VERSION 5.8 ;
BUSBITCHARS "[]" ;
DIVIDERCHAR "/" ;
UNITS
    DATABASE MICRONS 1000 ;
END UNITS

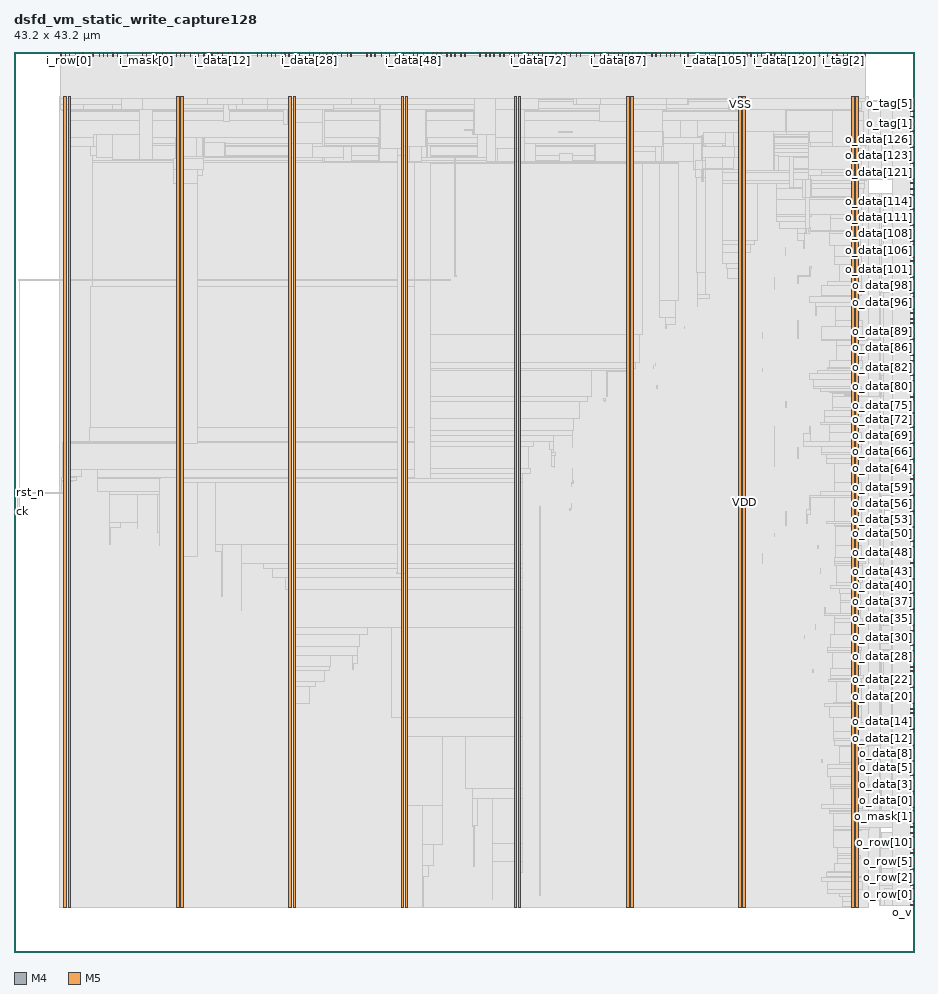
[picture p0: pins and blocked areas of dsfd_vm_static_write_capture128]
MACRO dsfd_vm_static_write_capture128
  FOREIGN dsfd_vm_static_write_capture128 0 0 ;
  CLASS BLOCK ;
  SIZE 43.2 BY 43.2 ;
  PIN ck
    DIRECTION INPUT ;
    USE SIGNAL ;
    PORT
      LAYER M4 ;
        RECT  0 21.12 0.192 21.144 ;
    END
  END ck
  PIN i_data[0]
    DIRECTION INPUT ;
    USE SIGNAL ;
    PORT
      LAYER M5 ;
        RECT  7.296 43.008 7.32 43.2 ;
    END
  END i_data[0]
  PIN i_data[100]
    DIRECTION INPUT ;
    USE SIGNAL ;
    PORT
      LAYER M5 ;
        RECT  31.968 43.008 31.992 43.2 ;
    END
  END i_data[100]
  PIN i_data[101]
    DIRECTION INPUT ;
    USE SIGNAL ;
    PORT
      LAYER M5 ;
        RECT  32.16 43.008 32.184 43.2 ;
    END
  END i_data[101]
  PIN i_data[102]
    DIRECTION INPUT ;
    USE SIGNAL ;
    PORT
      LAYER M5 ;
        RECT  32.352 43.008 32.376 43.2 ;
    END
  END i_data[102]
  PIN i_data[103]
    DIRECTION INPUT ;
    USE SIGNAL ;
    PORT
      LAYER M5 ;
        RECT  33.168 43.008 33.192 43.2 ;
    END
  END i_data[103]
  PIN i_data[104]
    DIRECTION INPUT ;
    USE SIGNAL ;
    PORT
      LAYER M5 ;
        RECT  33.36 43.008 33.384 43.2 ;
    END
  END i_data[104]
  PIN i_data[105]
    DIRECTION INPUT ;
    USE SIGNAL ;
    PORT
      LAYER M5 ;
        RECT  33.648 43.008 33.672 43.2 ;
    END
  END i_data[105]
  PIN i_data[106]
    DIRECTION INPUT ;
    USE SIGNAL ;
    PORT
      LAYER M5 ;
        RECT  33.84 43.008 33.864 43.2 ;
    END
  END i_data[106]
  PIN i_data[107]
    DIRECTION INPUT ;
    USE SIGNAL ;
    PORT
      LAYER M5 ;
        RECT  34.032 43.008 34.056 43.2 ;
    END
  END i_data[107]
  PIN i_data[108]
    DIRECTION INPUT ;
    USE SIGNAL ;
    PORT
      LAYER M5 ;
        RECT  34.32 43.008 34.344 43.2 ;
    END
  END i_data[108]
  PIN i_data[109]
    DIRECTION INPUT ;
    USE SIGNAL ;
    PORT
      LAYER M5 ;
        RECT  34.512 43.008 34.536 43.2 ;
    END
  END i_data[109]
  PIN i_data[10]
    DIRECTION INPUT ;
    USE SIGNAL ;
    PORT
      LAYER M5 ;
        RECT  9.504 43.008 9.528 43.2 ;
    END
  END i_data[10]
  PIN i_data[110]
    DIRECTION INPUT ;
    USE SIGNAL ;
    PORT
      LAYER M5 ;
        RECT  34.704 43.008 34.728 43.2 ;
    END
  END i_data[110]
  PIN i_data[111]
    DIRECTION INPUT ;
    USE SIGNAL ;
    PORT
      LAYER M5 ;
        RECT  34.992 43.008 35.016 43.2 ;
    END
  END i_data[111]
  PIN i_data[112]
    DIRECTION INPUT ;
    USE SIGNAL ;
    PORT
      LAYER M5 ;
        RECT  35.184 43.008 35.208 43.2 ;
    END
  END i_data[112]
  PIN i_data[113]
    DIRECTION INPUT ;
    USE SIGNAL ;
    PORT
      LAYER M5 ;
        RECT  35.376 43.008 35.4 43.2 ;
    END
  END i_data[113]
  PIN i_data[114]
    DIRECTION INPUT ;
    USE SIGNAL ;
    PORT
      LAYER M5 ;
        RECT  35.664 43.008 35.688 43.2 ;
    END
  END i_data[114]
  PIN i_data[115]
    DIRECTION INPUT ;
    USE SIGNAL ;
    PORT
      LAYER M5 ;
        RECT  35.856 43.008 35.88 43.2 ;
    END
  END i_data[115]
  PIN i_data[116]
    DIRECTION INPUT ;
    USE SIGNAL ;
    PORT
      LAYER M5 ;
        RECT  36.144 43.008 36.168 43.2 ;
    END
  END i_data[116]
  PIN i_data[117]
    DIRECTION INPUT ;
    USE SIGNAL ;
    PORT
      LAYER M5 ;
        RECT  36.336 43.008 36.36 43.2 ;
    END
  END i_data[117]
  PIN i_data[118]
    DIRECTION INPUT ;
    USE SIGNAL ;
    PORT
      LAYER M5 ;
        RECT  36.528 43.008 36.552 43.2 ;
    END
  END i_data[118]
  PIN i_data[119]
    DIRECTION INPUT ;
    USE SIGNAL ;
    PORT
      LAYER M5 ;
        RECT  36.816 43.008 36.84 43.2 ;
    END
  END i_data[119]
  PIN i_data[11]
    DIRECTION INPUT ;
    USE SIGNAL ;
    PORT
      LAYER M5 ;
        RECT  9.792 43.008 9.816 43.2 ;
    END
  END i_data[11]
  PIN i_data[120]
    DIRECTION INPUT ;
    USE SIGNAL ;
    PORT
      LAYER M5 ;
        RECT  37.008 43.008 37.032 43.2 ;
    END
  END i_data[120]
  PIN i_data[121]
    DIRECTION INPUT ;
    USE SIGNAL ;
    PORT
      LAYER M5 ;
        RECT  37.2 43.008 37.224 43.2 ;
    END
  END i_data[121]
  PIN i_data[122]
    DIRECTION INPUT ;
    USE SIGNAL ;
    PORT
      LAYER M5 ;
        RECT  37.488 43.008 37.512 43.2 ;
    END
  END i_data[122]
  PIN i_data[123]
    DIRECTION INPUT ;
    USE SIGNAL ;
    PORT
      LAYER M5 ;
        RECT  37.68 43.008 37.704 43.2 ;
    END
  END i_data[123]
  PIN i_data[124]
    DIRECTION INPUT ;
    USE SIGNAL ;
    PORT
      LAYER M5 ;
        RECT  37.872 43.008 37.896 43.2 ;
    END
  END i_data[124]
  PIN i_data[125]
    DIRECTION INPUT ;
    USE SIGNAL ;
    PORT
      LAYER M5 ;
        RECT  38.64 43.008 38.664 43.2 ;
    END
  END i_data[125]
  PIN i_data[126]
    DIRECTION INPUT ;
    USE SIGNAL ;
    PORT
      LAYER M5 ;
        RECT  38.832 43.008 38.856 43.2 ;
    END
  END i_data[126]
  PIN i_data[127]
    DIRECTION INPUT ;
    USE SIGNAL ;
    PORT
      LAYER M5 ;
        RECT  39.024 43.008 39.048 43.2 ;
    END
  END i_data[127]
  PIN i_data[12]
    DIRECTION INPUT ;
    USE SIGNAL ;
    PORT
      LAYER M5 ;
        RECT  9.984 43.008 10.008 43.2 ;
    END
  END i_data[12]
  PIN i_data[13]
    DIRECTION INPUT ;
    USE SIGNAL ;
    PORT
      LAYER M5 ;
        RECT  10.272 43.008 10.296 43.2 ;
    END
  END i_data[13]
  PIN i_data[14]
    DIRECTION INPUT ;
    USE SIGNAL ;
    PORT
      LAYER M5 ;
        RECT  10.464 43.008 10.488 43.2 ;
    END
  END i_data[14]
  PIN i_data[15]
    DIRECTION INPUT ;
    USE SIGNAL ;
    PORT
      LAYER M5 ;
        RECT  10.656 43.008 10.68 43.2 ;
    END
  END i_data[15]
  PIN i_data[16]
    DIRECTION INPUT ;
    USE SIGNAL ;
    PORT
      LAYER M5 ;
        RECT  10.944 43.008 10.968 43.2 ;
    END
  END i_data[16]
  PIN i_data[17]
    DIRECTION INPUT ;
    USE SIGNAL ;
    PORT
      LAYER M5 ;
        RECT  11.664 43.008 11.688 43.2 ;
    END
  END i_data[17]
  PIN i_data[18]
    DIRECTION INPUT ;
    USE SIGNAL ;
    PORT
      LAYER M5 ;
        RECT  11.856 43.008 11.88 43.2 ;
    END
  END i_data[18]
  PIN i_data[19]
    DIRECTION INPUT ;
    USE SIGNAL ;
    PORT
      LAYER M5 ;
        RECT  12.144 43.008 12.168 43.2 ;
    END
  END i_data[19]
  PIN i_data[1]
    DIRECTION INPUT ;
    USE SIGNAL ;
    PORT
      LAYER M5 ;
        RECT  7.488 43.008 7.512 43.2 ;
    END
  END i_data[1]
  PIN i_data[20]
    DIRECTION INPUT ;
    USE SIGNAL ;
    PORT
      LAYER M5 ;
        RECT  12.336 43.008 12.36 43.2 ;
    END
  END i_data[20]
  PIN i_data[21]
    DIRECTION INPUT ;
    USE SIGNAL ;
    PORT
      LAYER M5 ;
        RECT  12.528 43.008 12.552 43.2 ;
    END
  END i_data[21]
  PIN i_data[22]
    DIRECTION INPUT ;
    USE SIGNAL ;
    PORT
      LAYER M5 ;
        RECT  12.816 43.008 12.84 43.2 ;
    END
  END i_data[22]
  PIN i_data[23]
    DIRECTION INPUT ;
    USE SIGNAL ;
    PORT
      LAYER M5 ;
        RECT  13.008 43.008 13.032 43.2 ;
    END
  END i_data[23]
  PIN i_data[24]
    DIRECTION INPUT ;
    USE SIGNAL ;
    PORT
      LAYER M5 ;
        RECT  13.2 43.008 13.224 43.2 ;
    END
  END i_data[24]
  PIN i_data[25]
    DIRECTION INPUT ;
    USE SIGNAL ;
    PORT
      LAYER M5 ;
        RECT  13.488 43.008 13.512 43.2 ;
    END
  END i_data[25]
  PIN i_data[26]
    DIRECTION INPUT ;
    USE SIGNAL ;
    PORT
      LAYER M5 ;
        RECT  13.68 43.008 13.704 43.2 ;
    END
  END i_data[26]
  PIN i_data[27]
    DIRECTION INPUT ;
    USE SIGNAL ;
    PORT
      LAYER M5 ;
        RECT  13.968 43.008 13.992 43.2 ;
    END
  END i_data[27]
  PIN i_data[28]
    DIRECTION INPUT ;
    USE SIGNAL ;
    PORT
      LAYER M5 ;
        RECT  14.16 43.008 14.184 43.2 ;
    END
  END i_data[28]
  PIN i_data[29]
    DIRECTION INPUT ;
    USE SIGNAL ;
    PORT
      LAYER M5 ;
        RECT  14.352 43.008 14.376 43.2 ;
    END
  END i_data[29]
  PIN i_data[2]
    DIRECTION INPUT ;
    USE SIGNAL ;
    PORT
      LAYER M5 ;
        RECT  7.776 43.008 7.8 43.2 ;
    END
  END i_data[2]
  PIN i_data[30]
    DIRECTION INPUT ;
    USE SIGNAL ;
    PORT
      LAYER M5 ;
        RECT  14.64 43.008 14.664 43.2 ;
    END
  END i_data[30]
  PIN i_data[31]
    DIRECTION INPUT ;
    USE SIGNAL ;
    PORT
      LAYER M5 ;
        RECT  14.832 43.008 14.856 43.2 ;
    END
  END i_data[31]
  PIN i_data[32]
    DIRECTION INPUT ;
    USE SIGNAL ;
    PORT
      LAYER M5 ;
        RECT  15.024 43.008 15.048 43.2 ;
    END
  END i_data[32]
  PIN i_data[33]
    DIRECTION INPUT ;
    USE SIGNAL ;
    PORT
      LAYER M5 ;
        RECT  15.312 43.008 15.336 43.2 ;
    END
  END i_data[33]
  PIN i_data[34]
    DIRECTION INPUT ;
    USE SIGNAL ;
    PORT
      LAYER M5 ;
        RECT  15.504 43.008 15.528 43.2 ;
    END
  END i_data[34]
  PIN i_data[35]
    DIRECTION INPUT ;
    USE SIGNAL ;
    PORT
      LAYER M5 ;
        RECT  15.696 43.008 15.72 43.2 ;
    END
  END i_data[35]
  PIN i_data[36]
    DIRECTION INPUT ;
    USE SIGNAL ;
    PORT
      LAYER M5 ;
        RECT  15.984 43.008 16.008 43.2 ;
    END
  END i_data[36]
  PIN i_data[37]
    DIRECTION INPUT ;
    USE SIGNAL ;
    PORT
      LAYER M5 ;
        RECT  16.176 43.008 16.2 43.2 ;
    END
  END i_data[37]
  PIN i_data[38]
    DIRECTION INPUT ;
    USE SIGNAL ;
    PORT
      LAYER M5 ;
        RECT  16.944 43.008 16.968 43.2 ;
    END
  END i_data[38]
  PIN i_data[39]
    DIRECTION INPUT ;
    USE SIGNAL ;
    PORT
      LAYER M5 ;
        RECT  17.136 43.008 17.16 43.2 ;
    END
  END i_data[39]
  PIN i_data[3]
    DIRECTION INPUT ;
    USE SIGNAL ;
    PORT
      LAYER M5 ;
        RECT  7.968 43.008 7.992 43.2 ;
    END
  END i_data[3]
  PIN i_data[40]
    DIRECTION INPUT ;
    USE SIGNAL ;
    PORT
      LAYER M5 ;
        RECT  17.328 43.008 17.352 43.2 ;
    END
  END i_data[40]
  PIN i_data[41]
    DIRECTION INPUT ;
    USE SIGNAL ;
    PORT
      LAYER M5 ;
        RECT  17.616 43.008 17.64 43.2 ;
    END
  END i_data[41]
  PIN i_data[42]
    DIRECTION INPUT ;
    USE SIGNAL ;
    PORT
      LAYER M5 ;
        RECT  17.808 43.008 17.832 43.2 ;
    END
  END i_data[42]
  PIN i_data[43]
    DIRECTION INPUT ;
    USE SIGNAL ;
    PORT
      LAYER M5 ;
        RECT  18 43.008 18.024 43.2 ;
    END
  END i_data[43]
  PIN i_data[44]
    DIRECTION INPUT ;
    USE SIGNAL ;
    PORT
      LAYER M5 ;
        RECT  18.288 43.008 18.312 43.2 ;
    END
  END i_data[44]
  PIN i_data[45]
    DIRECTION INPUT ;
    USE SIGNAL ;
    PORT
      LAYER M5 ;
        RECT  18.48 43.008 18.504 43.2 ;
    END
  END i_data[45]
  PIN i_data[46]
    DIRECTION INPUT ;
    USE SIGNAL ;
    PORT
      LAYER M5 ;
        RECT  18.672 43.008 18.696 43.2 ;
    END
  END i_data[46]
  PIN i_data[47]
    DIRECTION INPUT ;
    USE SIGNAL ;
    PORT
      LAYER M5 ;
        RECT  18.96 43.008 18.984 43.2 ;
    END
  END i_data[47]
  PIN i_data[48]
    DIRECTION INPUT ;
    USE SIGNAL ;
    PORT
      LAYER M5 ;
        RECT  19.152 43.008 19.176 43.2 ;
    END
  END i_data[48]
  PIN i_data[49]
    DIRECTION INPUT ;
    USE SIGNAL ;
    PORT
      LAYER M5 ;
        RECT  19.344 43.008 19.368 43.2 ;
    END
  END i_data[49]
  PIN i_data[4]
    DIRECTION INPUT ;
    USE SIGNAL ;
    PORT
      LAYER M5 ;
        RECT  8.16 43.008 8.184 43.2 ;
    END
  END i_data[4]
  PIN i_data[50]
    DIRECTION INPUT ;
    USE SIGNAL ;
    PORT
      LAYER M5 ;
        RECT  19.632 43.008 19.656 43.2 ;
    END
  END i_data[50]
  PIN i_data[51]
    DIRECTION INPUT ;
    USE SIGNAL ;
    PORT
      LAYER M5 ;
        RECT  19.824 43.008 19.848 43.2 ;
    END
  END i_data[51]
  PIN i_data[52]
    DIRECTION INPUT ;
    USE SIGNAL ;
    PORT
      LAYER M5 ;
        RECT  20.112 43.008 20.136 43.2 ;
    END
  END i_data[52]
  PIN i_data[53]
    DIRECTION INPUT ;
    USE SIGNAL ;
    PORT
      LAYER M5 ;
        RECT  20.304 43.008 20.328 43.2 ;
    END
  END i_data[53]
  PIN i_data[54]
    DIRECTION INPUT ;
    USE SIGNAL ;
    PORT
      LAYER M5 ;
        RECT  20.496 43.008 20.52 43.2 ;
    END
  END i_data[54]
  PIN i_data[55]
    DIRECTION INPUT ;
    USE SIGNAL ;
    PORT
      LAYER M5 ;
        RECT  20.784 43.008 20.808 43.2 ;
    END
  END i_data[55]
  PIN i_data[56]
    DIRECTION INPUT ;
    USE SIGNAL ;
    PORT
      LAYER M5 ;
        RECT  20.976 43.008 21 43.2 ;
    END
  END i_data[56]
  PIN i_data[57]
    DIRECTION INPUT ;
    USE SIGNAL ;
    PORT
      LAYER M5 ;
        RECT  21.168 43.008 21.192 43.2 ;
    END
  END i_data[57]
  PIN i_data[58]
    DIRECTION INPUT ;
    USE SIGNAL ;
    PORT
      LAYER M5 ;
        RECT  21.456 43.008 21.48 43.2 ;
    END
  END i_data[58]
  PIN i_data[59]
    DIRECTION INPUT ;
    USE SIGNAL ;
    PORT
      LAYER M5 ;
        RECT  21.648 43.008 21.672 43.2 ;
    END
  END i_data[59]
  PIN i_data[5]
    DIRECTION INPUT ;
    USE SIGNAL ;
    PORT
      LAYER M5 ;
        RECT  8.448 43.008 8.472 43.2 ;
    END
  END i_data[5]
  PIN i_data[60]
    DIRECTION INPUT ;
    USE SIGNAL ;
    PORT
      LAYER M5 ;
        RECT  22.368 43.008 22.392 43.2 ;
    END
  END i_data[60]
  PIN i_data[61]
    DIRECTION INPUT ;
    USE SIGNAL ;
    PORT
      LAYER M5 ;
        RECT  22.656 43.008 22.68 43.2 ;
    END
  END i_data[61]
  PIN i_data[62]
    DIRECTION INPUT ;
    USE SIGNAL ;
    PORT
      LAYER M5 ;
        RECT  22.848 43.008 22.872 43.2 ;
    END
  END i_data[62]
  PIN i_data[63]
    DIRECTION INPUT ;
    USE SIGNAL ;
    PORT
      LAYER M5 ;
        RECT  23.04 43.008 23.064 43.2 ;
    END
  END i_data[63]
  PIN i_data[64]
    DIRECTION INPUT ;
    USE SIGNAL ;
    PORT
      LAYER M5 ;
        RECT  23.328 43.008 23.352 43.2 ;
    END
  END i_data[64]
  PIN i_data[65]
    DIRECTION INPUT ;
    USE SIGNAL ;
    PORT
      LAYER M5 ;
        RECT  23.52 43.008 23.544 43.2 ;
    END
  END i_data[65]
  PIN i_data[66]
    DIRECTION INPUT ;
    USE SIGNAL ;
    PORT
      LAYER M5 ;
        RECT  23.808 43.008 23.832 43.2 ;
    END
  END i_data[66]
  PIN i_data[67]
    DIRECTION INPUT ;
    USE SIGNAL ;
    PORT
      LAYER M5 ;
        RECT  24 43.008 24.024 43.2 ;
    END
  END i_data[67]
  PIN i_data[68]
    DIRECTION INPUT ;
    USE SIGNAL ;
    PORT
      LAYER M5 ;
        RECT  24.192 43.008 24.216 43.2 ;
    END
  END i_data[68]
  PIN i_data[69]
    DIRECTION INPUT ;
    USE SIGNAL ;
    PORT
      LAYER M5 ;
        RECT  24.48 43.008 24.504 43.2 ;
    END
  END i_data[69]
  PIN i_data[6]
    DIRECTION INPUT ;
    USE SIGNAL ;
    PORT
      LAYER M5 ;
        RECT  8.64 43.008 8.664 43.2 ;
    END
  END i_data[6]
  PIN i_data[70]
    DIRECTION INPUT ;
    USE SIGNAL ;
    PORT
      LAYER M5 ;
        RECT  24.672 43.008 24.696 43.2 ;
    END
  END i_data[70]
  PIN i_data[71]
    DIRECTION INPUT ;
    USE SIGNAL ;
    PORT
      LAYER M5 ;
        RECT  24.864 43.008 24.888 43.2 ;
    END
  END i_data[71]
  PIN i_data[72]
    DIRECTION INPUT ;
    USE SIGNAL ;
    PORT
      LAYER M5 ;
        RECT  25.152 43.008 25.176 43.2 ;
    END
  END i_data[72]
  PIN i_data[73]
    DIRECTION INPUT ;
    USE SIGNAL ;
    PORT
      LAYER M5 ;
        RECT  25.344 43.008 25.368 43.2 ;
    END
  END i_data[73]
  PIN i_data[74]
    DIRECTION INPUT ;
    USE SIGNAL ;
    PORT
      LAYER M5 ;
        RECT  25.536 43.008 25.56 43.2 ;
    END
  END i_data[74]
  PIN i_data[75]
    DIRECTION INPUT ;
    USE SIGNAL ;
    PORT
      LAYER M5 ;
        RECT  25.824 43.008 25.848 43.2 ;
    END
  END i_data[75]
  PIN i_data[76]
    DIRECTION INPUT ;
    USE SIGNAL ;
    PORT
      LAYER M5 ;
        RECT  26.016 43.008 26.04 43.2 ;
    END
  END i_data[76]
  PIN i_data[77]
    DIRECTION INPUT ;
    USE SIGNAL ;
    PORT
      LAYER M5 ;
        RECT  26.304 43.008 26.328 43.2 ;
    END
  END i_data[77]
  PIN i_data[78]
    DIRECTION INPUT ;
    USE SIGNAL ;
    PORT
      LAYER M5 ;
        RECT  26.496 43.008 26.52 43.2 ;
    END
  END i_data[78]
  PIN i_data[79]
    DIRECTION INPUT ;
    USE SIGNAL ;
    PORT
      LAYER M5 ;
        RECT  26.688 43.008 26.712 43.2 ;
    END
  END i_data[79]
  PIN i_data[7]
    DIRECTION INPUT ;
    USE SIGNAL ;
    PORT
      LAYER M5 ;
        RECT  8.832 43.008 8.856 43.2 ;
    END
  END i_data[7]
  PIN i_data[80]
    DIRECTION INPUT ;
    USE SIGNAL ;
    PORT
      LAYER M5 ;
        RECT  26.976 43.008 27 43.2 ;
    END
  END i_data[80]
  PIN i_data[81]
    DIRECTION INPUT ;
    USE SIGNAL ;
    PORT
      LAYER M5 ;
        RECT  27.168 43.008 27.192 43.2 ;
    END
  END i_data[81]
  PIN i_data[82]
    DIRECTION INPUT ;
    USE SIGNAL ;
    PORT
      LAYER M5 ;
        RECT  27.84 43.008 27.864 43.2 ;
    END
  END i_data[82]
  PIN i_data[83]
    DIRECTION INPUT ;
    USE SIGNAL ;
    PORT
      LAYER M5 ;
        RECT  28.128 43.008 28.152 43.2 ;
    END
  END i_data[83]
  PIN i_data[84]
    DIRECTION INPUT ;
    USE SIGNAL ;
    PORT
      LAYER M5 ;
        RECT  28.32 43.008 28.344 43.2 ;
    END
  END i_data[84]
  PIN i_data[85]
    DIRECTION INPUT ;
    USE SIGNAL ;
    PORT
      LAYER M5 ;
        RECT  28.512 43.008 28.536 43.2 ;
    END
  END i_data[85]
  PIN i_data[86]
    DIRECTION INPUT ;
    USE SIGNAL ;
    PORT
      LAYER M5 ;
        RECT  28.8 43.008 28.824 43.2 ;
    END
  END i_data[86]
  PIN i_data[87]
    DIRECTION INPUT ;
    USE SIGNAL ;
    PORT
      LAYER M5 ;
        RECT  28.992 43.008 29.016 43.2 ;
    END
  END i_data[87]
  PIN i_data[88]
    DIRECTION INPUT ;
    USE SIGNAL ;
    PORT
      LAYER M5 ;
        RECT  29.184 43.008 29.208 43.2 ;
    END
  END i_data[88]
  PIN i_data[89]
    DIRECTION INPUT ;
    USE SIGNAL ;
    PORT
      LAYER M5 ;
        RECT  29.472 43.008 29.496 43.2 ;
    END
  END i_data[89]
  PIN i_data[8]
    DIRECTION INPUT ;
    USE SIGNAL ;
    PORT
      LAYER M5 ;
        RECT  9.12 43.008 9.144 43.2 ;
    END
  END i_data[8]
  PIN i_data[90]
    DIRECTION INPUT ;
    USE SIGNAL ;
    PORT
      LAYER M5 ;
        RECT  29.664 43.008 29.688 43.2 ;
    END
  END i_data[90]
  PIN i_data[91]
    DIRECTION INPUT ;
    USE SIGNAL ;
    PORT
      LAYER M5 ;
        RECT  29.952 43.008 29.976 43.2 ;
    END
  END i_data[91]
  PIN i_data[92]
    DIRECTION INPUT ;
    USE SIGNAL ;
    PORT
      LAYER M5 ;
        RECT  30.144 43.008 30.168 43.2 ;
    END
  END i_data[92]
  PIN i_data[93]
    DIRECTION INPUT ;
    USE SIGNAL ;
    PORT
      LAYER M5 ;
        RECT  30.336 43.008 30.36 43.2 ;
    END
  END i_data[93]
  PIN i_data[94]
    DIRECTION INPUT ;
    USE SIGNAL ;
    PORT
      LAYER M5 ;
        RECT  30.624 43.008 30.648 43.2 ;
    END
  END i_data[94]
  PIN i_data[95]
    DIRECTION INPUT ;
    USE SIGNAL ;
    PORT
      LAYER M5 ;
        RECT  30.816 43.008 30.84 43.2 ;
    END
  END i_data[95]
  PIN i_data[96]
    DIRECTION INPUT ;
    USE SIGNAL ;
    PORT
      LAYER M5 ;
        RECT  31.008 43.008 31.032 43.2 ;
    END
  END i_data[96]
  PIN i_data[97]
    DIRECTION INPUT ;
    USE SIGNAL ;
    PORT
      LAYER M5 ;
        RECT  31.296 43.008 31.32 43.2 ;
    END
  END i_data[97]
  PIN i_data[98]
    DIRECTION INPUT ;
    USE SIGNAL ;
    PORT
      LAYER M5 ;
        RECT  31.488 43.008 31.512 43.2 ;
    END
  END i_data[98]
  PIN i_data[99]
    DIRECTION INPUT ;
    USE SIGNAL ;
    PORT
      LAYER M5 ;
        RECT  31.68 43.008 31.704 43.2 ;
    END
  END i_data[99]
  PIN i_data[9]
    DIRECTION INPUT ;
    USE SIGNAL ;
    PORT
      LAYER M5 ;
        RECT  9.312 43.008 9.336 43.2 ;
    END
  END i_data[9]
  PIN i_mask[0]
    DIRECTION INPUT ;
    USE SIGNAL ;
    PORT
      LAYER M5 ;
        RECT  6.336 43.008 6.36 43.2 ;
    END
  END i_mask[0]
  PIN i_mask[1]
    DIRECTION INPUT ;
    USE SIGNAL ;
    PORT
      LAYER M5 ;
        RECT  6.624 43.008 6.648 43.2 ;
    END
  END i_mask[1]
  PIN i_mask[2]
    DIRECTION INPUT ;
    USE SIGNAL ;
    PORT
      LAYER M5 ;
        RECT  6.816 43.008 6.84 43.2 ;
    END
  END i_mask[2]
  PIN i_mask[3]
    DIRECTION INPUT ;
    USE SIGNAL ;
    PORT
      LAYER M5 ;
        RECT  7.104 43.008 7.128 43.2 ;
    END
  END i_mask[3]
  PIN i_row[0]
    DIRECTION INPUT ;
    USE SIGNAL ;
    PORT
      LAYER M5 ;
        RECT  2.64 43.008 2.664 43.2 ;
    END
  END i_row[0]
  PIN i_row[10]
    DIRECTION INPUT ;
    USE SIGNAL ;
    PORT
      LAYER M5 ;
        RECT  4.944 43.008 4.968 43.2 ;
    END
  END i_row[10]
  PIN i_row[11]
    DIRECTION INPUT ;
    USE SIGNAL ;
    PORT
      LAYER M5 ;
        RECT  5.136 43.008 5.16 43.2 ;
    END
  END i_row[11]
  PIN i_row[12]
    DIRECTION INPUT ;
    USE SIGNAL ;
    PORT
      LAYER M5 ;
        RECT  5.424 43.008 5.448 43.2 ;
    END
  END i_row[12]
  PIN i_row[13]
    DIRECTION INPUT ;
    USE SIGNAL ;
    PORT
      LAYER M5 ;
        RECT  6.144 43.008 6.168 43.2 ;
    END
  END i_row[13]
  PIN i_row[1]
    DIRECTION INPUT ;
    USE SIGNAL ;
    PORT
      LAYER M5 ;
        RECT  2.928 43.008 2.952 43.2 ;
    END
  END i_row[1]
  PIN i_row[2]
    DIRECTION INPUT ;
    USE SIGNAL ;
    PORT
      LAYER M5 ;
        RECT  3.12 43.008 3.144 43.2 ;
    END
  END i_row[2]
  PIN i_row[3]
    DIRECTION INPUT ;
    USE SIGNAL ;
    PORT
      LAYER M5 ;
        RECT  3.312 43.008 3.336 43.2 ;
    END
  END i_row[3]
  PIN i_row[4]
    DIRECTION INPUT ;
    USE SIGNAL ;
    PORT
      LAYER M5 ;
        RECT  3.6 43.008 3.624 43.2 ;
    END
  END i_row[4]
  PIN i_row[5]
    DIRECTION INPUT ;
    USE SIGNAL ;
    PORT
      LAYER M5 ;
        RECT  3.792 43.008 3.816 43.2 ;
    END
  END i_row[5]
  PIN i_row[6]
    DIRECTION INPUT ;
    USE SIGNAL ;
    PORT
      LAYER M5 ;
        RECT  4.08 43.008 4.104 43.2 ;
    END
  END i_row[6]
  PIN i_row[7]
    DIRECTION INPUT ;
    USE SIGNAL ;
    PORT
      LAYER M5 ;
        RECT  4.272 43.008 4.296 43.2 ;
    END
  END i_row[7]
  PIN i_row[8]
    DIRECTION INPUT ;
    USE SIGNAL ;
    PORT
      LAYER M5 ;
        RECT  4.464 43.008 4.488 43.2 ;
    END
  END i_row[8]
  PIN i_row[9]
    DIRECTION INPUT ;
    USE SIGNAL ;
    PORT
      LAYER M5 ;
        RECT  4.752 43.008 4.776 43.2 ;
    END
  END i_row[9]
  PIN i_tag[0]
    DIRECTION INPUT ;
    USE SIGNAL ;
    PORT
      LAYER M5 ;
        RECT  39.312 43.008 39.336 43.2 ;
    END
  END i_tag[0]
  PIN i_tag[1]
    DIRECTION INPUT ;
    USE SIGNAL ;
    PORT
      LAYER M5 ;
        RECT  39.504 43.008 39.528 43.2 ;
    END
  END i_tag[1]
  PIN i_tag[2]
    DIRECTION INPUT ;
    USE SIGNAL ;
    PORT
      LAYER M5 ;
        RECT  39.792 43.008 39.816 43.2 ;
    END
  END i_tag[2]
  PIN i_tag[3]
    DIRECTION INPUT ;
    USE SIGNAL ;
    PORT
      LAYER M5 ;
        RECT  39.984 43.008 40.008 43.2 ;
    END
  END i_tag[3]
  PIN i_tag[4]
    DIRECTION INPUT ;
    USE SIGNAL ;
    PORT
      LAYER M5 ;
        RECT  40.176 43.008 40.2 43.2 ;
    END
  END i_tag[4]
  PIN i_tag[5]
    DIRECTION INPUT ;
    USE SIGNAL ;
    PORT
      LAYER M5 ;
        RECT  40.464 43.008 40.488 43.2 ;
    END
  END i_tag[5]
  PIN i_tag[6]
    DIRECTION INPUT ;
    USE SIGNAL ;
    PORT
      LAYER M5 ;
        RECT  40.656 43.008 40.68 43.2 ;
    END
  END i_tag[6]
  PIN i_tag[7]
    DIRECTION INPUT ;
    USE SIGNAL ;
    PORT
      LAYER M5 ;
        RECT  40.848 43.008 40.872 43.2 ;
    END
  END i_tag[7]
  PIN i_v
    DIRECTION INPUT ;
    USE SIGNAL ;
    PORT
      LAYER M5 ;
        RECT  2.256 43.008 2.28 43.2 ;
    END
  END i_v
  PIN i_we
    DIRECTION INPUT ;
    USE SIGNAL ;
    PORT
      LAYER M5 ;
        RECT  2.448 43.008 2.472 43.2 ;
    END
  END i_we
  PIN o_data[0]
    DIRECTION OUTPUT ;
    USE SIGNAL ;
    PORT
      LAYER M4 ;
        RECT  43.008 7.248 43.2 7.272 ;
    END
  END o_data[0]
  PIN o_data[100]
    DIRECTION OUTPUT ;
    USE SIGNAL ;
    PORT
      LAYER M4 ;
        RECT  43.008 32.112 43.2 32.136 ;
    END
  END o_data[100]
  PIN o_data[101]
    DIRECTION OUTPUT ;
    USE SIGNAL ;
    PORT
      LAYER M4 ;
        RECT  43.008 32.4 43.2 32.424 ;
    END
  END o_data[101]
  PIN o_data[102]
    DIRECTION OUTPUT ;
    USE SIGNAL ;
    PORT
      LAYER M4 ;
        RECT  43.008 32.688 43.2 32.712 ;
    END
  END o_data[102]
  PIN o_data[103]
    DIRECTION OUTPUT ;
    USE SIGNAL ;
    PORT
      LAYER M4 ;
        RECT  43.008 32.88 43.2 32.904 ;
    END
  END o_data[103]
  PIN o_data[104]
    DIRECTION OUTPUT ;
    USE SIGNAL ;
    PORT
      LAYER M4 ;
        RECT  43.008 33.168 43.2 33.192 ;
    END
  END o_data[104]
  PIN o_data[105]
    DIRECTION OUTPUT ;
    USE SIGNAL ;
    PORT
      LAYER M4 ;
        RECT  43.008 33.36 43.2 33.384 ;
    END
  END o_data[105]
  PIN o_data[106]
    DIRECTION OUTPUT ;
    USE SIGNAL ;
    PORT
      LAYER M4 ;
        RECT  43.008 33.648 43.2 33.672 ;
    END
  END o_data[106]
  PIN o_data[107]
    DIRECTION OUTPUT ;
    USE SIGNAL ;
    PORT
      LAYER M4 ;
        RECT  43.008 33.936 43.2 33.96 ;
    END
  END o_data[107]
  PIN o_data[108]
    DIRECTION OUTPUT ;
    USE SIGNAL ;
    PORT
      LAYER M4 ;
        RECT  43.008 34.128 43.2 34.152 ;
    END
  END o_data[108]
  PIN o_data[109]
    DIRECTION OUTPUT ;
    USE SIGNAL ;
    PORT
      LAYER M4 ;
        RECT  43.008 34.416 43.2 34.44 ;
    END
  END o_data[109]
  PIN o_data[10]
    DIRECTION OUTPUT ;
    USE SIGNAL ;
    PORT
      LAYER M4 ;
        RECT  43.008 9.744 43.2 9.768 ;
    END
  END o_data[10]
  PIN o_data[110]
    DIRECTION OUTPUT ;
    USE SIGNAL ;
    PORT
      LAYER M4 ;
        RECT  43.008 34.608 43.2 34.632 ;
    END
  END o_data[110]
  PIN o_data[111]
    DIRECTION OUTPUT ;
    USE SIGNAL ;
    PORT
      LAYER M4 ;
        RECT  43.008 34.896 43.2 34.92 ;
    END
  END o_data[111]
  PIN o_data[112]
    DIRECTION OUTPUT ;
    USE SIGNAL ;
    PORT
      LAYER M4 ;
        RECT  43.008 35.088 43.2 35.112 ;
    END
  END o_data[112]
  PIN o_data[113]
    DIRECTION OUTPUT ;
    USE SIGNAL ;
    PORT
      LAYER M4 ;
        RECT  43.008 35.376 43.2 35.4 ;
    END
  END o_data[113]
  PIN o_data[114]
    DIRECTION OUTPUT ;
    USE SIGNAL ;
    PORT
      LAYER M4 ;
        RECT  43.008 35.664 43.2 35.688 ;
    END
  END o_data[114]
  PIN o_data[115]
    DIRECTION OUTPUT ;
    USE SIGNAL ;
    PORT
      LAYER M4 ;
        RECT  43.008 35.856 43.2 35.88 ;
    END
  END o_data[115]
  PIN o_data[116]
    DIRECTION OUTPUT ;
    USE SIGNAL ;
    PORT
      LAYER M4 ;
        RECT  43.008 36.144 43.2 36.168 ;
    END
  END o_data[116]
  PIN o_data[117]
    DIRECTION OUTPUT ;
    USE SIGNAL ;
    PORT
      LAYER M4 ;
        RECT  43.008 36.336 43.2 36.36 ;
    END
  END o_data[117]
  PIN o_data[118]
    DIRECTION OUTPUT ;
    USE SIGNAL ;
    PORT
      LAYER M4 ;
        RECT  43.008 36.624 43.2 36.648 ;
    END
  END o_data[118]
  PIN o_data[119]
    DIRECTION OUTPUT ;
    USE SIGNAL ;
    PORT
      LAYER M4 ;
        RECT  43.008 36.912 43.2 36.936 ;
    END
  END o_data[119]
  PIN o_data[11]
    DIRECTION OUTPUT ;
    USE SIGNAL ;
    PORT
      LAYER M4 ;
        RECT  43.008 9.936 43.2 9.96 ;
    END
  END o_data[11]
  PIN o_data[120]
    DIRECTION OUTPUT ;
    USE SIGNAL ;
    PORT
      LAYER M4 ;
        RECT  43.008 37.104 43.2 37.128 ;
    END
  END o_data[120]
  PIN o_data[121]
    DIRECTION OUTPUT ;
    USE SIGNAL ;
    PORT
      LAYER M4 ;
        RECT  43.008 37.392 43.2 37.416 ;
    END
  END o_data[121]
  PIN o_data[122]
    DIRECTION OUTPUT ;
    USE SIGNAL ;
    PORT
      LAYER M4 ;
        RECT  43.008 37.584 43.2 37.608 ;
    END
  END o_data[122]
  PIN o_data[123]
    DIRECTION OUTPUT ;
    USE SIGNAL ;
    PORT
      LAYER M4 ;
        RECT  43.008 37.872 43.2 37.896 ;
    END
  END o_data[123]
  PIN o_data[124]
    DIRECTION OUTPUT ;
    USE SIGNAL ;
    PORT
      LAYER M4 ;
        RECT  43.008 38.16 43.2 38.184 ;
    END
  END o_data[124]
  PIN o_data[125]
    DIRECTION OUTPUT ;
    USE SIGNAL ;
    PORT
      LAYER M4 ;
        RECT  43.008 38.352 43.2 38.376 ;
    END
  END o_data[125]
  PIN o_data[126]
    DIRECTION OUTPUT ;
    USE SIGNAL ;
    PORT
      LAYER M4 ;
        RECT  43.008 38.64 43.2 38.664 ;
    END
  END o_data[126]
  PIN o_data[127]
    DIRECTION OUTPUT ;
    USE SIGNAL ;
    PORT
      LAYER M4 ;
        RECT  43.008 38.832 43.2 38.856 ;
    END
  END o_data[127]
  PIN o_data[12]
    DIRECTION OUTPUT ;
    USE SIGNAL ;
    PORT
      LAYER M4 ;
        RECT  43.008 10.224 43.2 10.248 ;
    END
  END o_data[12]
  PIN o_data[13]
    DIRECTION OUTPUT ;
    USE SIGNAL ;
    PORT
      LAYER M4 ;
        RECT  43.008 10.416 43.2 10.44 ;
    END
  END o_data[13]
  PIN o_data[14]
    DIRECTION OUTPUT ;
    USE SIGNAL ;
    PORT
      LAYER M4 ;
        RECT  43.008 10.704 43.2 10.728 ;
    END
  END o_data[14]
  PIN o_data[15]
    DIRECTION OUTPUT ;
    USE SIGNAL ;
    PORT
      LAYER M4 ;
        RECT  43.008 10.992 43.2 11.016 ;
    END
  END o_data[15]
  PIN o_data[16]
    DIRECTION OUTPUT ;
    USE SIGNAL ;
    PORT
      LAYER M4 ;
        RECT  43.008 11.184 43.2 11.208 ;
    END
  END o_data[16]
  PIN o_data[17]
    DIRECTION OUTPUT ;
    USE SIGNAL ;
    PORT
      LAYER M4 ;
        RECT  43.008 11.472 43.2 11.496 ;
    END
  END o_data[17]
  PIN o_data[18]
    DIRECTION OUTPUT ;
    USE SIGNAL ;
    PORT
      LAYER M4 ;
        RECT  43.008 11.664 43.2 11.688 ;
    END
  END o_data[18]
  PIN o_data[19]
    DIRECTION OUTPUT ;
    USE SIGNAL ;
    PORT
      LAYER M4 ;
        RECT  43.008 11.952 43.2 11.976 ;
    END
  END o_data[19]
  PIN o_data[1]
    DIRECTION OUTPUT ;
    USE SIGNAL ;
    PORT
      LAYER M4 ;
        RECT  43.008 7.44 43.2 7.464 ;
    END
  END o_data[1]
  PIN o_data[20]
    DIRECTION OUTPUT ;
    USE SIGNAL ;
    PORT
      LAYER M4 ;
        RECT  43.008 12.24 43.2 12.264 ;
    END
  END o_data[20]
  PIN o_data[21]
    DIRECTION OUTPUT ;
    USE SIGNAL ;
    PORT
      LAYER M4 ;
        RECT  43.008 12.432 43.2 12.456 ;
    END
  END o_data[21]
  PIN o_data[22]
    DIRECTION OUTPUT ;
    USE SIGNAL ;
    PORT
      LAYER M4 ;
        RECT  43.008 12.72 43.2 12.744 ;
    END
  END o_data[22]
  PIN o_data[23]
    DIRECTION OUTPUT ;
    USE SIGNAL ;
    PORT
      LAYER M4 ;
        RECT  43.008 12.912 43.2 12.936 ;
    END
  END o_data[23]
  PIN o_data[24]
    DIRECTION OUTPUT ;
    USE SIGNAL ;
    PORT
      LAYER M4 ;
        RECT  43.008 13.2 43.2 13.224 ;
    END
  END o_data[24]
  PIN o_data[25]
    DIRECTION OUTPUT ;
    USE SIGNAL ;
    PORT
      LAYER M4 ;
        RECT  43.008 13.488 43.2 13.512 ;
    END
  END o_data[25]
  PIN o_data[26]
    DIRECTION OUTPUT ;
    USE SIGNAL ;
    PORT
      LAYER M4 ;
        RECT  43.008 13.68 43.2 13.704 ;
    END
  END o_data[26]
  PIN o_data[27]
    DIRECTION OUTPUT ;
    USE SIGNAL ;
    PORT
      LAYER M4 ;
        RECT  43.008 13.968 43.2 13.992 ;
    END
  END o_data[27]
  PIN o_data[28]
    DIRECTION OUTPUT ;
    USE SIGNAL ;
    PORT
      LAYER M4 ;
        RECT  43.008 14.16 43.2 14.184 ;
    END
  END o_data[28]
  PIN o_data[29]
    DIRECTION OUTPUT ;
    USE SIGNAL ;
    PORT
      LAYER M4 ;
        RECT  43.008 14.448 43.2 14.472 ;
    END
  END o_data[29]
  PIN o_data[2]
    DIRECTION OUTPUT ;
    USE SIGNAL ;
    PORT
      LAYER M4 ;
        RECT  43.008 7.728 43.2 7.752 ;
    END
  END o_data[2]
  PIN o_data[30]
    DIRECTION OUTPUT ;
    USE SIGNAL ;
    PORT
      LAYER M4 ;
        RECT  43.008 14.736 43.2 14.76 ;
    END
  END o_data[30]
  PIN o_data[31]
    DIRECTION OUTPUT ;
    USE SIGNAL ;
    PORT
      LAYER M4 ;
        RECT  43.008 14.928 43.2 14.952 ;
    END
  END o_data[31]
  PIN o_data[32]
    DIRECTION OUTPUT ;
    USE SIGNAL ;
    PORT
      LAYER M4 ;
        RECT  43.008 15.216 43.2 15.24 ;
    END
  END o_data[32]
  PIN o_data[33]
    DIRECTION OUTPUT ;
    USE SIGNAL ;
    PORT
      LAYER M4 ;
        RECT  43.008 15.408 43.2 15.432 ;
    END
  END o_data[33]
  PIN o_data[34]
    DIRECTION OUTPUT ;
    USE SIGNAL ;
    PORT
      LAYER M4 ;
        RECT  43.008 15.696 43.2 15.72 ;
    END
  END o_data[34]
  PIN o_data[35]
    DIRECTION OUTPUT ;
    USE SIGNAL ;
    PORT
      LAYER M4 ;
        RECT  43.008 15.984 43.2 16.008 ;
    END
  END o_data[35]
  PIN o_data[36]
    DIRECTION OUTPUT ;
    USE SIGNAL ;
    PORT
      LAYER M4 ;
        RECT  43.008 16.176 43.2 16.2 ;
    END
  END o_data[36]
  PIN o_data[37]
    DIRECTION OUTPUT ;
    USE SIGNAL ;
    PORT
      LAYER M4 ;
        RECT  43.008 16.464 43.2 16.488 ;
    END
  END o_data[37]
  PIN o_data[38]
    DIRECTION OUTPUT ;
    USE SIGNAL ;
    PORT
      LAYER M4 ;
        RECT  43.008 16.656 43.2 16.68 ;
    END
  END o_data[38]
  PIN o_data[39]
    DIRECTION OUTPUT ;
    USE SIGNAL ;
    PORT
      LAYER M4 ;
        RECT  43.008 16.944 43.2 16.968 ;
    END
  END o_data[39]
  PIN o_data[3]
    DIRECTION OUTPUT ;
    USE SIGNAL ;
    PORT
      LAYER M4 ;
        RECT  43.008 8.016 43.2 8.04 ;
    END
  END o_data[3]
  PIN o_data[40]
    DIRECTION OUTPUT ;
    USE SIGNAL ;
    PORT
      LAYER M4 ;
        RECT  43.008 17.232 43.2 17.256 ;
    END
  END o_data[40]
  PIN o_data[41]
    DIRECTION OUTPUT ;
    USE SIGNAL ;
    PORT
      LAYER M4 ;
        RECT  43.008 17.424 43.2 17.448 ;
    END
  END o_data[41]
  PIN o_data[42]
    DIRECTION OUTPUT ;
    USE SIGNAL ;
    PORT
      LAYER M4 ;
        RECT  43.008 17.712 43.2 17.736 ;
    END
  END o_data[42]
  PIN o_data[43]
    DIRECTION OUTPUT ;
    USE SIGNAL ;
    PORT
      LAYER M4 ;
        RECT  43.008 17.904 43.2 17.928 ;
    END
  END o_data[43]
  PIN o_data[44]
    DIRECTION OUTPUT ;
    USE SIGNAL ;
    PORT
      LAYER M4 ;
        RECT  43.008 18.192 43.2 18.216 ;
    END
  END o_data[44]
  PIN o_data[45]
    DIRECTION OUTPUT ;
    USE SIGNAL ;
    PORT
      LAYER M4 ;
        RECT  43.008 18.48 43.2 18.504 ;
    END
  END o_data[45]
  PIN o_data[46]
    DIRECTION OUTPUT ;
    USE SIGNAL ;
    PORT
      LAYER M4 ;
        RECT  43.008 18.672 43.2 18.696 ;
    END
  END o_data[46]
  PIN o_data[47]
    DIRECTION OUTPUT ;
    USE SIGNAL ;
    PORT
      LAYER M4 ;
        RECT  43.008 18.96 43.2 18.984 ;
    END
  END o_data[47]
  PIN o_data[48]
    DIRECTION OUTPUT ;
    USE SIGNAL ;
    PORT
      LAYER M4 ;
        RECT  43.008 19.152 43.2 19.176 ;
    END
  END o_data[48]
  PIN o_data[49]
    DIRECTION OUTPUT ;
    USE SIGNAL ;
    PORT
      LAYER M4 ;
        RECT  43.008 19.44 43.2 19.464 ;
    END
  END o_data[49]
  PIN o_data[4]
    DIRECTION OUTPUT ;
    USE SIGNAL ;
    PORT
      LAYER M4 ;
        RECT  43.008 8.208 43.2 8.232 ;
    END
  END o_data[4]
  PIN o_data[50]
    DIRECTION OUTPUT ;
    USE SIGNAL ;
    PORT
      LAYER M4 ;
        RECT  43.008 19.728 43.2 19.752 ;
    END
  END o_data[50]
  PIN o_data[51]
    DIRECTION OUTPUT ;
    USE SIGNAL ;
    PORT
      LAYER M4 ;
        RECT  43.008 19.92 43.2 19.944 ;
    END
  END o_data[51]
  PIN o_data[52]
    DIRECTION OUTPUT ;
    USE SIGNAL ;
    PORT
      LAYER M4 ;
        RECT  43.008 20.208 43.2 20.232 ;
    END
  END o_data[52]
  PIN o_data[53]
    DIRECTION OUTPUT ;
    USE SIGNAL ;
    PORT
      LAYER M4 ;
        RECT  43.008 20.4 43.2 20.424 ;
    END
  END o_data[53]
  PIN o_data[54]
    DIRECTION OUTPUT ;
    USE SIGNAL ;
    PORT
      LAYER M4 ;
        RECT  43.008 20.688 43.2 20.712 ;
    END
  END o_data[54]
  PIN o_data[55]
    DIRECTION OUTPUT ;
    USE SIGNAL ;
    PORT
      LAYER M4 ;
        RECT  43.008 20.976 43.2 21 ;
    END
  END o_data[55]
  PIN o_data[56]
    DIRECTION OUTPUT ;
    USE SIGNAL ;
    PORT
      LAYER M4 ;
        RECT  43.008 21.168 43.2 21.192 ;
    END
  END o_data[56]
  PIN o_data[57]
    DIRECTION OUTPUT ;
    USE SIGNAL ;
    PORT
      LAYER M4 ;
        RECT  43.008 21.456 43.2 21.48 ;
    END
  END o_data[57]
  PIN o_data[58]
    DIRECTION OUTPUT ;
    USE SIGNAL ;
    PORT
      LAYER M4 ;
        RECT  43.008 21.648 43.2 21.672 ;
    END
  END o_data[58]
  PIN o_data[59]
    DIRECTION OUTPUT ;
    USE SIGNAL ;
    PORT
      LAYER M4 ;
        RECT  43.008 21.936 43.2 21.96 ;
    END
  END o_data[59]
  PIN o_data[5]
    DIRECTION OUTPUT ;
    USE SIGNAL ;
    PORT
      LAYER M4 ;
        RECT  43.008 8.496 43.2 8.52 ;
    END
  END o_data[5]
  PIN o_data[60]
    DIRECTION OUTPUT ;
    USE SIGNAL ;
    PORT
      LAYER M4 ;
        RECT  43.008 22.128 43.2 22.152 ;
    END
  END o_data[60]
  PIN o_data[61]
    DIRECTION OUTPUT ;
    USE SIGNAL ;
    PORT
      LAYER M4 ;
        RECT  43.008 22.416 43.2 22.44 ;
    END
  END o_data[61]
  PIN o_data[62]
    DIRECTION OUTPUT ;
    USE SIGNAL ;
    PORT
      LAYER M4 ;
        RECT  43.008 22.704 43.2 22.728 ;
    END
  END o_data[62]
  PIN o_data[63]
    DIRECTION OUTPUT ;
    USE SIGNAL ;
    PORT
      LAYER M4 ;
        RECT  43.008 22.896 43.2 22.92 ;
    END
  END o_data[63]
  PIN o_data[64]
    DIRECTION OUTPUT ;
    USE SIGNAL ;
    PORT
      LAYER M4 ;
        RECT  43.008 23.184 43.2 23.208 ;
    END
  END o_data[64]
  PIN o_data[65]
    DIRECTION OUTPUT ;
    USE SIGNAL ;
    PORT
      LAYER M4 ;
        RECT  43.008 23.376 43.2 23.4 ;
    END
  END o_data[65]
  PIN o_data[66]
    DIRECTION OUTPUT ;
    USE SIGNAL ;
    PORT
      LAYER M4 ;
        RECT  43.008 23.664 43.2 23.688 ;
    END
  END o_data[66]
  PIN o_data[67]
    DIRECTION OUTPUT ;
    USE SIGNAL ;
    PORT
      LAYER M4 ;
        RECT  43.008 23.952 43.2 23.976 ;
    END
  END o_data[67]
  PIN o_data[68]
    DIRECTION OUTPUT ;
    USE SIGNAL ;
    PORT
      LAYER M4 ;
        RECT  43.008 24.144 43.2 24.168 ;
    END
  END o_data[68]
  PIN o_data[69]
    DIRECTION OUTPUT ;
    USE SIGNAL ;
    PORT
      LAYER M4 ;
        RECT  43.008 24.432 43.2 24.456 ;
    END
  END o_data[69]
  PIN o_data[6]
    DIRECTION OUTPUT ;
    USE SIGNAL ;
    PORT
      LAYER M4 ;
        RECT  43.008 8.688 43.2 8.712 ;
    END
  END o_data[6]
  PIN o_data[70]
    DIRECTION OUTPUT ;
    USE SIGNAL ;
    PORT
      LAYER M4 ;
        RECT  43.008 24.624 43.2 24.648 ;
    END
  END o_data[70]
  PIN o_data[71]
    DIRECTION OUTPUT ;
    USE SIGNAL ;
    PORT
      LAYER M4 ;
        RECT  43.008 24.912 43.2 24.936 ;
    END
  END o_data[71]
  PIN o_data[72]
    DIRECTION OUTPUT ;
    USE SIGNAL ;
    PORT
      LAYER M4 ;
        RECT  43.008 25.2 43.2 25.224 ;
    END
  END o_data[72]
  PIN o_data[73]
    DIRECTION OUTPUT ;
    USE SIGNAL ;
    PORT
      LAYER M4 ;
        RECT  43.008 25.392 43.2 25.416 ;
    END
  END o_data[73]
  PIN o_data[74]
    DIRECTION OUTPUT ;
    USE SIGNAL ;
    PORT
      LAYER M4 ;
        RECT  43.008 25.68 43.2 25.704 ;
    END
  END o_data[74]
  PIN o_data[75]
    DIRECTION OUTPUT ;
    USE SIGNAL ;
    PORT
      LAYER M4 ;
        RECT  43.008 25.872 43.2 25.896 ;
    END
  END o_data[75]
  PIN o_data[76]
    DIRECTION OUTPUT ;
    USE SIGNAL ;
    PORT
      LAYER M4 ;
        RECT  43.008 26.16 43.2 26.184 ;
    END
  END o_data[76]
  PIN o_data[77]
    DIRECTION OUTPUT ;
    USE SIGNAL ;
    PORT
      LAYER M4 ;
        RECT  43.008 26.448 43.2 26.472 ;
    END
  END o_data[77]
  PIN o_data[78]
    DIRECTION OUTPUT ;
    USE SIGNAL ;
    PORT
      LAYER M4 ;
        RECT  43.008 26.64 43.2 26.664 ;
    END
  END o_data[78]
  PIN o_data[79]
    DIRECTION OUTPUT ;
    USE SIGNAL ;
    PORT
      LAYER M4 ;
        RECT  43.008 26.928 43.2 26.952 ;
    END
  END o_data[79]
  PIN o_data[7]
    DIRECTION OUTPUT ;
    USE SIGNAL ;
    PORT
      LAYER M4 ;
        RECT  43.008 8.976 43.2 9 ;
    END
  END o_data[7]
  PIN o_data[80]
    DIRECTION OUTPUT ;
    USE SIGNAL ;
    PORT
      LAYER M4 ;
        RECT  43.008 27.12 43.2 27.144 ;
    END
  END o_data[80]
  PIN o_data[81]
    DIRECTION OUTPUT ;
    USE SIGNAL ;
    PORT
      LAYER M4 ;
        RECT  43.008 27.408 43.2 27.432 ;
    END
  END o_data[81]
  PIN o_data[82]
    DIRECTION OUTPUT ;
    USE SIGNAL ;
    PORT
      LAYER M4 ;
        RECT  43.008 27.696 43.2 27.72 ;
    END
  END o_data[82]
  PIN o_data[83]
    DIRECTION OUTPUT ;
    USE SIGNAL ;
    PORT
      LAYER M4 ;
        RECT  43.008 27.888 43.2 27.912 ;
    END
  END o_data[83]
  PIN o_data[84]
    DIRECTION OUTPUT ;
    USE SIGNAL ;
    PORT
      LAYER M4 ;
        RECT  43.008 28.176 43.2 28.2 ;
    END
  END o_data[84]
  PIN o_data[85]
    DIRECTION OUTPUT ;
    USE SIGNAL ;
    PORT
      LAYER M4 ;
        RECT  43.008 28.368 43.2 28.392 ;
    END
  END o_data[85]
  PIN o_data[86]
    DIRECTION OUTPUT ;
    USE SIGNAL ;
    PORT
      LAYER M4 ;
        RECT  43.008 28.656 43.2 28.68 ;
    END
  END o_data[86]
  PIN o_data[87]
    DIRECTION OUTPUT ;
    USE SIGNAL ;
    PORT
      LAYER M4 ;
        RECT  43.008 28.944 43.2 28.968 ;
    END
  END o_data[87]
  PIN o_data[88]
    DIRECTION OUTPUT ;
    USE SIGNAL ;
    PORT
      LAYER M4 ;
        RECT  43.008 29.136 43.2 29.16 ;
    END
  END o_data[88]
  PIN o_data[89]
    DIRECTION OUTPUT ;
    USE SIGNAL ;
    PORT
      LAYER M4 ;
        RECT  43.008 29.424 43.2 29.448 ;
    END
  END o_data[89]
  PIN o_data[8]
    DIRECTION OUTPUT ;
    USE SIGNAL ;
    PORT
      LAYER M4 ;
        RECT  43.008 9.168 43.2 9.192 ;
    END
  END o_data[8]
  PIN o_data[90]
    DIRECTION OUTPUT ;
    USE SIGNAL ;
    PORT
      LAYER M4 ;
        RECT  43.008 29.616 43.2 29.64 ;
    END
  END o_data[90]
  PIN o_data[91]
    DIRECTION OUTPUT ;
    USE SIGNAL ;
    PORT
      LAYER M4 ;
        RECT  43.008 29.904 43.2 29.928 ;
    END
  END o_data[91]
  PIN o_data[92]
    DIRECTION OUTPUT ;
    USE SIGNAL ;
    PORT
      LAYER M4 ;
        RECT  43.008 30.192 43.2 30.216 ;
    END
  END o_data[92]
  PIN o_data[93]
    DIRECTION OUTPUT ;
    USE SIGNAL ;
    PORT
      LAYER M4 ;
        RECT  43.008 30.384 43.2 30.408 ;
    END
  END o_data[93]
  PIN o_data[94]
    DIRECTION OUTPUT ;
    USE SIGNAL ;
    PORT
      LAYER M4 ;
        RECT  43.008 30.672 43.2 30.696 ;
    END
  END o_data[94]
  PIN o_data[95]
    DIRECTION OUTPUT ;
    USE SIGNAL ;
    PORT
      LAYER M4 ;
        RECT  43.008 30.864 43.2 30.888 ;
    END
  END o_data[95]
  PIN o_data[96]
    DIRECTION OUTPUT ;
    USE SIGNAL ;
    PORT
      LAYER M4 ;
        RECT  43.008 31.152 43.2 31.176 ;
    END
  END o_data[96]
  PIN o_data[97]
    DIRECTION OUTPUT ;
    USE SIGNAL ;
    PORT
      LAYER M4 ;
        RECT  43.008 31.44 43.2 31.464 ;
    END
  END o_data[97]
  PIN o_data[98]
    DIRECTION OUTPUT ;
    USE SIGNAL ;
    PORT
      LAYER M4 ;
        RECT  43.008 31.632 43.2 31.656 ;
    END
  END o_data[98]
  PIN o_data[99]
    DIRECTION OUTPUT ;
    USE SIGNAL ;
    PORT
      LAYER M4 ;
        RECT  43.008 31.92 43.2 31.944 ;
    END
  END o_data[99]
  PIN o_data[9]
    DIRECTION OUTPUT ;
    USE SIGNAL ;
    PORT
      LAYER M4 ;
        RECT  43.008 9.456 43.2 9.48 ;
    END
  END o_data[9]
  PIN o_mask[0]
    DIRECTION OUTPUT ;
    USE SIGNAL ;
    PORT
      LAYER M4 ;
        RECT  43.008 6.192 43.2 6.216 ;
    END
  END o_mask[0]
  PIN o_mask[1]
    DIRECTION OUTPUT ;
    USE SIGNAL ;
    PORT
      LAYER M4 ;
        RECT  43.008 6.48 43.2 6.504 ;
    END
  END o_mask[1]
  PIN o_mask[2]
    DIRECTION OUTPUT ;
    USE SIGNAL ;
    PORT
      LAYER M4 ;
        RECT  43.008 6.768 43.2 6.792 ;
    END
  END o_mask[2]
  PIN o_mask[3]
    DIRECTION OUTPUT ;
    USE SIGNAL ;
    PORT
      LAYER M4 ;
        RECT  43.008 6.96 43.2 6.984 ;
    END
  END o_mask[3]
  PIN o_row[0]
    DIRECTION OUTPUT ;
    USE SIGNAL ;
    PORT
      LAYER M4 ;
        RECT  43.008 2.736 43.2 2.76 ;
    END
  END o_row[0]
  PIN o_row[10]
    DIRECTION OUTPUT ;
    USE SIGNAL ;
    PORT
      LAYER M4 ;
        RECT  43.008 5.232 43.2 5.256 ;
    END
  END o_row[10]
  PIN o_row[11]
    DIRECTION OUTPUT ;
    USE SIGNAL ;
    PORT
      LAYER M4 ;
        RECT  43.008 5.52 43.2 5.544 ;
    END
  END o_row[11]
  PIN o_row[12]
    DIRECTION OUTPUT ;
    USE SIGNAL ;
    PORT
      LAYER M4 ;
        RECT  43.008 5.712 43.2 5.736 ;
    END
  END o_row[12]
  PIN o_row[13]
    DIRECTION OUTPUT ;
    USE SIGNAL ;
    PORT
      LAYER M4 ;
        RECT  43.008 6 43.2 6.024 ;
    END
  END o_row[13]
  PIN o_row[1]
    DIRECTION OUTPUT ;
    USE SIGNAL ;
    PORT
      LAYER M4 ;
        RECT  43.008 3.024 43.2 3.048 ;
    END
  END o_row[1]
  PIN o_row[2]
    DIRECTION OUTPUT ;
    USE SIGNAL ;
    PORT
      LAYER M4 ;
        RECT  43.008 3.216 43.2 3.24 ;
    END
  END o_row[2]
  PIN o_row[3]
    DIRECTION OUTPUT ;
    USE SIGNAL ;
    PORT
      LAYER M4 ;
        RECT  43.008 3.504 43.2 3.528 ;
    END
  END o_row[3]
  PIN o_row[4]
    DIRECTION OUTPUT ;
    USE SIGNAL ;
    PORT
      LAYER M4 ;
        RECT  43.008 3.696 43.2 3.72 ;
    END
  END o_row[4]
  PIN o_row[5]
    DIRECTION OUTPUT ;
    USE SIGNAL ;
    PORT
      LAYER M4 ;
        RECT  43.008 3.984 43.2 4.008 ;
    END
  END o_row[5]
  PIN o_row[6]
    DIRECTION OUTPUT ;
    USE SIGNAL ;
    PORT
      LAYER M4 ;
        RECT  43.008 4.272 43.2 4.296 ;
    END
  END o_row[6]
  PIN o_row[7]
    DIRECTION OUTPUT ;
    USE SIGNAL ;
    PORT
      LAYER M4 ;
        RECT  43.008 4.464 43.2 4.488 ;
    END
  END o_row[7]
  PIN o_row[8]
    DIRECTION OUTPUT ;
    USE SIGNAL ;
    PORT
      LAYER M4 ;
        RECT  43.008 4.752 43.2 4.776 ;
    END
  END o_row[8]
  PIN o_row[9]
    DIRECTION OUTPUT ;
    USE SIGNAL ;
    PORT
      LAYER M4 ;
        RECT  43.008 4.944 43.2 4.968 ;
    END
  END o_row[9]
  PIN o_tag[0]
    DIRECTION OUTPUT ;
    USE SIGNAL ;
    PORT
      LAYER M4 ;
        RECT  43.008 39.12 43.2 39.144 ;
    END
  END o_tag[0]
  PIN o_tag[1]
    DIRECTION OUTPUT ;
    USE SIGNAL ;
    PORT
      LAYER M4 ;
        RECT  43.008 39.408 43.2 39.432 ;
    END
  END o_tag[1]
  PIN o_tag[2]
    DIRECTION OUTPUT ;
    USE SIGNAL ;
    PORT
      LAYER M4 ;
        RECT  43.008 39.6 43.2 39.624 ;
    END
  END o_tag[2]
  PIN o_tag[3]
    DIRECTION OUTPUT ;
    USE SIGNAL ;
    PORT
      LAYER M4 ;
        RECT  43.008 39.888 43.2 39.912 ;
    END
  END o_tag[3]
  PIN o_tag[4]
    DIRECTION OUTPUT ;
    USE SIGNAL ;
    PORT
      LAYER M4 ;
        RECT  43.008 40.08 43.2 40.104 ;
    END
  END o_tag[4]
  PIN o_tag[5]
    DIRECTION OUTPUT ;
    USE SIGNAL ;
    PORT
      LAYER M4 ;
        RECT  43.008 40.368 43.2 40.392 ;
    END
  END o_tag[5]
  PIN o_tag[6]
    DIRECTION OUTPUT ;
    USE SIGNAL ;
    PORT
      LAYER M4 ;
        RECT  43.008 40.656 43.2 40.68 ;
    END
  END o_tag[6]
  PIN o_tag[7]
    DIRECTION OUTPUT ;
    USE SIGNAL ;
    PORT
      LAYER M4 ;
        RECT  43.008 40.848 43.2 40.872 ;
    END
  END o_tag[7]
  PIN o_v
    DIRECTION OUTPUT ;
    USE SIGNAL ;
    PORT
      LAYER M4 ;
        RECT  43.008 2.256 43.2 2.28 ;
    END
  END o_v
  PIN o_we
    DIRECTION OUTPUT ;
    USE SIGNAL ;
    PORT
      LAYER M4 ;
        RECT  43.008 2.448 43.2 2.472 ;
    END
  END o_we
  PIN rst_n
    DIRECTION INPUT ;
    USE SIGNAL ;
    PORT
      LAYER M4 ;
        RECT  0 22.032 0.192 22.056 ;
    END
  END rst_n
  PIN VDD
    DIRECTION INOUT ;
    USE POWER ;
    PORT
      LAYER M5 ;
        RECT  40.392 2.151 40.512 41.049 ;
        RECT  34.992 2.151 35.112 41.049 ;
        RECT  29.592 2.151 29.712 41.049 ;
        RECT  24.192 2.151 24.312 41.049 ;
        RECT  18.792 2.151 18.912 41.049 ;
        RECT  13.392 2.151 13.512 41.049 ;
        RECT  7.992 2.151 8.112 41.049 ;
        RECT  2.592 2.151 2.712 41.049 ;
    END
  END VDD
  PIN VSS
    DIRECTION INOUT ;
    USE GROUND ;
    PORT
      LAYER M5 ;
        RECT  40.2 2.137 40.32 41.063 ;
        RECT  34.8 2.137 34.92 41.063 ;
        RECT  29.4 2.137 29.52 41.063 ;
        RECT  24 2.137 24.12 41.063 ;
        RECT  18.6 2.137 18.72 41.063 ;
        RECT  13.2 2.137 13.32 41.063 ;
        RECT  7.8 2.137 7.92 41.063 ;
        RECT  2.4 2.137 2.52 41.063 ;
    END
  END VSS
  # OT_OBS_CLOSED layer=M5 d_um=1.536 added=29
  OBS
    LAYER RVTN ;
     RECT  2.16 2.16 41.04 2.295 ;
     RECT  2.16 2.565 41.04 2.835 ;
     RECT  2.16 3.105 41.04 3.375 ;
     RECT  2.16 3.645 41.04 3.915 ;
     RECT  2.16 4.185 41.04 4.455 ;
     RECT  2.16 4.725 41.04 4.995 ;
     RECT  2.16 5.265 41.04 5.535 ;
     RECT  2.16 5.805 41.04 6.075 ;
     RECT  2.16 6.345 41.04 6.615 ;
     RECT  2.16 6.885 41.04 7.155 ;
     RECT  2.16 7.425 41.04 7.695 ;
     RECT  2.16 7.965 41.04 8.235 ;
     RECT  2.16 8.505 41.04 8.775 ;
     RECT  2.16 9.045 41.04 9.315 ;
     RECT  2.16 9.585 41.04 9.855 ;
     RECT  2.16 10.125 41.04 10.395 ;
     RECT  2.16 10.665 41.04 10.935 ;
     RECT  2.16 11.205 41.04 11.475 ;
     RECT  2.16 11.745 41.04 12.015 ;
     RECT  2.16 12.285 41.04 12.555 ;
     RECT  2.16 12.825 41.04 13.095 ;
     RECT  2.16 13.365 41.04 13.635 ;
     RECT  2.16 13.905 41.04 14.175 ;
     RECT  2.16 14.445 41.04 14.715 ;
     RECT  2.16 14.985 41.04 15.255 ;
     RECT  2.16 15.525 41.04 15.795 ;
     RECT  2.16 16.065 41.04 16.335 ;
     RECT  2.16 16.605 41.04 16.875 ;
     RECT  2.16 17.145 41.04 17.415 ;
     RECT  2.16 17.685 41.04 17.955 ;
     RECT  2.16 18.225 41.04 18.495 ;
     RECT  2.16 18.765 41.04 19.035 ;
     RECT  2.16 19.305 41.04 19.575 ;
     RECT  2.16 19.845 41.04 20.115 ;
     RECT  2.16 20.385 41.04 20.655 ;
     RECT  2.16 20.925 41.04 21.195 ;
     RECT  2.16 21.465 41.04 21.735 ;
     RECT  2.16 22.005 41.04 22.275 ;
     RECT  2.16 22.545 41.04 22.815 ;
     RECT  2.16 23.085 41.04 23.355 ;
     RECT  2.16 23.625 41.04 23.895 ;
     RECT  2.16 24.165 41.04 24.435 ;
     RECT  2.16 24.705 41.04 24.975 ;
     RECT  2.16 25.245 41.04 25.515 ;
     RECT  2.16 25.785 41.04 26.055 ;
     RECT  2.16 26.325 41.04 26.595 ;
     RECT  2.16 26.865 41.04 27.135 ;
     RECT  2.16 27.405 41.04 27.675 ;
     RECT  2.16 27.945 41.04 28.215 ;
     RECT  2.16 28.485 41.04 28.755 ;
     RECT  2.16 29.025 41.04 29.295 ;
     RECT  2.16 29.565 41.04 29.835 ;
     RECT  2.16 30.105 41.04 30.375 ;
     RECT  2.16 30.645 41.04 30.915 ;
     RECT  2.16 31.185 41.04 31.455 ;
     RECT  2.16 31.725 41.04 31.995 ;
     RECT  2.16 32.265 41.04 32.535 ;
     RECT  2.16 32.805 41.04 33.075 ;
     RECT  2.16 33.345 41.04 33.615 ;
     RECT  2.16 33.885 41.04 34.155 ;
     RECT  2.16 34.425 41.04 34.695 ;
     RECT  2.16 34.965 41.04 35.235 ;
     RECT  2.16 35.505 41.04 35.775 ;
     RECT  2.16 36.045 41.04 36.315 ;
     RECT  2.16 36.585 41.04 36.855 ;
     RECT  2.16 37.125 41.04 37.395 ;
     RECT  2.16 37.665 41.04 37.935 ;
     RECT  2.16 38.205 41.04 38.475 ;
     RECT  2.16 38.745 41.04 39.015 ;
     RECT  2.16 39.285 41.04 39.555 ;
     RECT  2.16 39.825 41.04 40.095 ;
     RECT  2.16 40.365 41.04 40.635 ;
     RECT  2.16 40.905 41.04 41.04 ;
    LAYER RVTP ;
     RECT  2.16 2.295 41.04 2.565 ;
     RECT  2.16 2.835 41.04 3.105 ;
     RECT  2.16 3.375 41.04 3.645 ;
     RECT  2.16 3.915 41.04 4.185 ;
     RECT  2.16 4.455 41.04 4.725 ;
     RECT  2.16 4.995 41.04 5.265 ;
     RECT  2.16 5.535 41.04 5.805 ;
     RECT  2.16 6.075 41.04 6.345 ;
     RECT  2.16 6.615 41.04 6.885 ;
     RECT  2.16 7.155 41.04 7.425 ;
     RECT  2.16 7.695 41.04 7.965 ;
     RECT  2.16 8.235 41.04 8.505 ;
     RECT  2.16 8.775 41.04 9.045 ;
     RECT  2.16 9.315 41.04 9.585 ;
     RECT  2.16 9.855 41.04 10.125 ;
     RECT  2.16 10.395 41.04 10.665 ;
     RECT  2.16 10.935 41.04 11.205 ;
     RECT  2.16 11.475 41.04 11.745 ;
     RECT  2.16 12.015 41.04 12.285 ;
     RECT  2.16 12.555 41.04 12.825 ;
     RECT  2.16 13.095 41.04 13.365 ;
     RECT  2.16 13.635 41.04 13.905 ;
     RECT  2.16 14.175 41.04 14.445 ;
     RECT  2.16 14.715 41.04 14.985 ;
     RECT  2.16 15.255 41.04 15.525 ;
     RECT  2.16 15.795 41.04 16.065 ;
     RECT  2.16 16.335 41.04 16.605 ;
     RECT  2.16 16.875 41.04 17.145 ;
     RECT  2.16 17.415 41.04 17.685 ;
     RECT  2.16 17.955 41.04 18.225 ;
     RECT  2.16 18.495 41.04 18.765 ;
     RECT  2.16 19.035 41.04 19.305 ;
     RECT  2.16 19.575 41.04 19.845 ;
     RECT  2.16 20.115 41.04 20.385 ;
     RECT  2.16 20.655 41.04 20.925 ;
     RECT  2.16 21.195 41.04 21.465 ;
     RECT  2.16 21.735 41.04 22.005 ;
     RECT  2.16 22.275 41.04 22.545 ;
     RECT  2.16 22.815 41.04 23.085 ;
     RECT  2.16 23.355 41.04 23.625 ;
     RECT  2.16 23.895 41.04 24.165 ;
     RECT  2.16 24.435 41.04 24.705 ;
     RECT  2.16 24.975 41.04 25.245 ;
     RECT  2.16 25.515 41.04 25.785 ;
     RECT  2.16 26.055 41.04 26.325 ;
     RECT  2.16 26.595 41.04 26.865 ;
     RECT  2.16 27.135 41.04 27.405 ;
     RECT  2.16 27.675 41.04 27.945 ;
     RECT  2.16 28.215 41.04 28.485 ;
     RECT  2.16 28.755 41.04 29.025 ;
     RECT  2.16 29.295 41.04 29.565 ;
     RECT  2.16 29.835 41.04 30.105 ;
     RECT  2.16 30.375 41.04 30.645 ;
     RECT  2.16 30.915 41.04 31.185 ;
     RECT  2.16 31.455 41.04 31.725 ;
     RECT  2.16 31.995 41.04 32.265 ;
     RECT  2.16 32.535 41.04 32.805 ;
     RECT  2.16 33.075 41.04 33.345 ;
     RECT  2.16 33.615 41.04 33.885 ;
     RECT  2.16 34.155 41.04 34.425 ;
     RECT  2.16 34.695 41.04 34.965 ;
     RECT  2.16 35.235 41.04 35.505 ;
     RECT  2.16 35.775 41.04 36.045 ;
     RECT  2.16 36.315 41.04 36.585 ;
     RECT  2.16 36.855 41.04 37.125 ;
     RECT  2.16 37.395 41.04 37.665 ;
     RECT  2.16 37.935 41.04 38.205 ;
     RECT  2.16 38.475 41.04 38.745 ;
     RECT  2.16 39.015 41.04 39.285 ;
     RECT  2.16 39.555 41.04 39.825 ;
     RECT  2.16 40.095 41.04 40.365 ;
     RECT  2.16 40.635 41.04 40.905 ;
    LAYER M1 ;
     RECT  2.16 2.151 41.04 41.049 ;
    LAYER M2 ;
     RECT  2.16 2.151 41.04 41.049 ;
     RECT  41.04 2.466 41.567 36.414 ;
     RECT  41.567 2.466 41.603 29.628 ;
     RECT  41.603 2.466 41.639 5.724 ;
     RECT  41.603 6.516 41.639 29.628 ;
     RECT  41.567 30.456 41.639 36.414 ;
     RECT  41.04 37.404 41.639 40.464 ;
     RECT  41.639 8.856 41.783 9.684 ;
     RECT  41.639 19.746 41.783 21.654 ;
     RECT  41.639 10.836 42.143 18.99 ;
     RECT  41.783 21.204 42.143 21.654 ;
     RECT  41.639 2.466 42.179 3.744 ;
     RECT  41.639 4.896 42.179 5.724 ;
     RECT  41.639 6.516 42.179 7.884 ;
     RECT  42.143 10.836 42.179 15.444 ;
     RECT  42.143 16.236 42.179 18.99 ;
     RECT  41.783 19.746 42.179 19.764 ;
     RECT  42.143 21.276 42.179 21.654 ;
     RECT  41.639 22.446 42.179 28.674 ;
     RECT  41.639 30.546 42.179 30.744 ;
     RECT  41.639 31.896 42.179 36.414 ;
     RECT  41.639 37.404 42.179 40.014 ;
     RECT  42.179 2.736 42.215 3.744 ;
     RECT  42.179 6.822 42.215 6.84 ;
     RECT  41.783 9.09 42.215 9.684 ;
     RECT  42.179 11.376 42.215 11.97 ;
     RECT  42.179 12.834 42.215 13.59 ;
     RECT  42.179 14.526 42.215 14.544 ;
     RECT  42.179 16.506 42.215 17.676 ;
     RECT  42.179 21.276 42.215 21.294 ;
     RECT  42.179 23.904 42.215 24.498 ;
     RECT  42.179 27.918 42.215 27.936 ;
     RECT  42.179 30.726 42.215 30.744 ;
     RECT  42.179 33.426 42.215 33.444 ;
     RECT  42.179 34.74 42.215 36.414 ;
     RECT  42.179 37.404 42.215 37.62 ;
     RECT  42.179 38.484 42.215 39.114 ;
     RECT  42.215 3.186 42.251 3.204 ;
     RECT  42.215 35.514 42.251 35.532 ;
     RECT  42.215 37.404 42.251 37.422 ;
     RECT  42.215 11.376 43.007 11.394 ;
     RECT  42.179 31.896 43.007 31.914 ;
     RECT  42.215 38.484 43.043 38.502 ;
    LAYER M3 ;
     RECT  40.215 2.143 40.305 2.191 ;
     RECT  2.415 2.143 2.505 2.413 ;
     RECT  7.815 2.143 7.905 2.413 ;
     RECT  13.215 2.143 13.305 2.413 ;
     RECT  18.615 2.143 18.705 2.413 ;
     RECT  24.015 2.143 24.105 2.413 ;
     RECT  29.415 2.143 29.505 2.413 ;
     RECT  34.815 2.143 34.905 2.413 ;
     RECT  39.78 2.191 40.305 2.413 ;
     RECT  41.544 2.251 41.562 2.443 ;
     RECT  39.78 2.413 40.497 2.641 ;
     RECT  41.544 2.443 42.174 2.731 ;
     RECT  39.6 2.641 40.497 2.803 ;
     RECT  39.06 2.803 40.497 3.001 ;
     RECT  41.544 2.731 42.21 3.181 ;
     RECT  39.06 3.001 40.734 3.379 ;
     RECT  38.772 3.379 40.734 3.569 ;
     RECT  38.988 3.569 40.734 3.605 ;
     RECT  19.62 2.191 19.638 3.613 ;
     RECT  41.544 3.181 42.246 3.677 ;
     RECT  41.616 3.677 42.246 3.725 ;
     RECT  24.015 2.413 24.297 3.811 ;
     RECT  38.988 3.605 40.554 3.839 ;
     RECT  39.06 3.839 40.554 3.875 ;
     RECT  41.616 3.725 42.21 4.013 ;
     RECT  19.62 3.613 19.89 4.153 ;
     RECT  39.384 3.875 40.554 4.253 ;
     RECT  22.968 2.497 22.986 4.351 ;
     RECT  24.015 3.811 24.39 4.351 ;
     RECT  39.528 4.253 40.554 4.495 ;
     RECT  39.528 4.495 40.626 4.649 ;
     RECT  39.528 4.649 40.554 4.721 ;
     RECT  41.616 4.013 41.634 4.747 ;
     RECT  41.616 4.747 42.174 4.973 ;
     RECT  39.528 4.721 40.497 5.035 ;
     RECT  19.62 4.153 20.142 5.161 ;
     RECT  22.968 4.351 24.39 5.197 ;
     RECT  34.815 2.413 35.097 5.197 ;
     RECT  34.776 5.197 35.097 5.297 ;
     RECT  42.156 4.973 42.174 5.741 ;
     RECT  39.348 5.035 40.497 5.845 ;
     RECT  39.348 5.845 40.698 5.881 ;
     RECT  22.068 4.117 22.086 6.007 ;
     RECT  39.348 5.881 41.058 6.029 ;
     RECT  22.032 6.007 22.086 6.043 ;
     RECT  21.996 6.043 22.086 6.079 ;
     RECT  41.58 6.187 41.598 6.269 ;
     RECT  39.348 6.029 40.497 6.655 ;
     RECT  39.168 6.655 40.497 6.763 ;
     RECT  39.168 6.763 40.842 6.809 ;
     RECT  42.156 6.475 42.174 6.817 ;
     RECT  39.168 6.809 40.734 6.889 ;
     RECT  42.156 6.817 42.21 6.989 ;
     RECT  18.615 2.413 18.897 7.051 ;
     RECT  19.62 5.161 20.574 7.051 ;
     RECT  38.772 6.889 40.734 7.079 ;
     RECT  21.996 6.079 22.23 7.357 ;
     RECT  22.968 5.197 24.426 7.357 ;
     RECT  21.996 7.357 24.426 7.861 ;
     RECT  39.348 7.079 40.554 7.861 ;
     RECT  42.156 6.989 42.174 7.889 ;
     RECT  39.204 7.861 40.698 7.961 ;
     RECT  39.204 7.961 40.554 8.045 ;
     RECT  39.204 8.045 40.497 8.401 ;
     RECT  34.815 5.297 35.097 8.707 ;
     RECT  39.06 8.401 40.497 8.815 ;
     RECT  34.776 8.707 35.097 8.843 ;
     RECT  39.06 8.815 40.626 9.005 ;
     RECT  41.616 8.131 41.778 9.005 ;
     RECT  39.6 9.005 40.626 9.085 ;
     RECT  38.772 9.085 38.79 9.239 ;
     RECT  42.156 9.085 42.21 9.773 ;
     RECT  39.6 9.085 40.698 9.859 ;
     RECT  39.6 9.859 41.058 9.895 ;
     RECT  39.384 9.895 41.058 9.925 ;
     RECT  39.384 9.925 41.634 10.165 ;
     RECT  39.348 10.165 41.634 10.253 ;
     RECT  18.615 7.051 20.574 10.327 ;
     RECT  21.672 7.861 24.426 10.327 ;
     RECT  41.616 10.253 41.634 10.499 ;
     RECT  39.348 10.253 40.734 10.589 ;
     RECT  18.615 10.327 24.426 11.245 ;
     RECT  39.348 10.589 40.698 11.245 ;
     RECT  42.984 11.371 43.002 11.501 ;
     RECT  39.132 11.245 40.698 11.785 ;
     RECT  13.215 2.413 13.497 11.911 ;
     RECT  38.916 11.785 40.698 11.939 ;
     RECT  42.156 10.699 42.174 11.947 ;
     RECT  39.348 11.939 40.698 11.975 ;
     RECT  42.12 11.947 42.21 12.427 ;
     RECT  13.215 11.911 14.166 12.757 ;
     RECT  13.215 12.757 14.49 12.991 ;
     RECT  39.456 11.975 40.698 12.991 ;
     RECT  39.096 12.991 40.698 13.091 ;
     RECT  39.204 13.091 40.698 13.135 ;
     RECT  41.76 12.427 42.21 13.195 ;
     RECT  39.204 13.135 40.77 13.289 ;
     RECT  13.215 12.991 14.886 13.531 ;
     RECT  38.34 13.405 38.358 13.559 ;
     RECT  34.815 8.843 35.097 13.567 ;
     RECT  39.204 13.289 40.626 13.631 ;
     RECT  34.776 13.567 35.097 13.667 ;
     RECT  41.724 13.195 42.21 13.709 ;
     RECT  13.215 13.531 15.138 13.711 ;
     RECT  16.272 13.567 16.29 13.837 ;
     RECT  41.724 13.709 42.174 13.981 ;
     RECT  13.215 13.711 15.174 14.215 ;
     RECT  16.272 13.837 16.506 14.215 ;
     RECT  39.276 13.631 40.626 14.377 ;
     RECT  41.616 13.981 42.174 14.443 ;
     RECT  39.024 14.377 40.626 14.485 ;
     RECT  41.58 14.443 42.174 14.521 ;
     RECT  39.024 14.485 40.698 14.639 ;
     RECT  13.215 14.215 16.506 14.647 ;
     RECT  41.58 14.521 42.21 14.819 ;
     RECT  42.12 14.819 42.21 14.957 ;
     RECT  37.944 15.061 37.962 15.215 ;
     RECT  13.215 14.647 16.578 15.223 ;
     RECT  39.204 14.639 40.497 15.251 ;
     RECT  13.215 15.223 16.974 15.565 ;
     RECT  18.108 11.245 24.426 15.565 ;
     RECT  42.12 14.957 42.174 15.691 ;
     RECT  38.448 15.493 38.466 15.719 ;
     RECT  34.815 13.667 35.097 15.727 ;
     RECT  39.384 15.251 40.497 15.835 ;
     RECT  34.776 15.727 35.097 15.863 ;
     RECT  39.384 15.835 40.734 15.989 ;
     RECT  39.384 15.989 40.626 16.141 ;
     RECT  38.916 16.141 40.626 16.259 ;
     RECT  41.58 15.691 42.174 16.501 ;
     RECT  38.916 16.259 38.934 16.529 ;
     RECT  39.672 16.259 40.626 16.771 ;
     RECT  39.672 16.771 40.698 16.871 ;
     RECT  39.672 16.871 40.626 17.185 ;
     RECT  13.215 15.565 24.426 17.383 ;
     RECT  39.6 17.185 40.626 17.455 ;
     RECT  41.58 16.501 42.21 17.519 ;
     RECT  39.204 17.455 40.626 17.609 ;
     RECT  39.456 17.609 40.626 17.725 ;
     RECT  41.76 17.519 42.21 17.741 ;
     RECT  13.032 17.383 24.426 17.959 ;
     RECT  12.384 17.959 24.426 18.391 ;
     RECT  38.7 18.157 38.718 18.419 ;
     RECT  39.456 17.725 40.734 18.535 ;
     RECT  10.908 16.375 10.926 18.661 ;
     RECT  11.952 18.391 24.426 18.661 ;
     RECT  39.384 18.535 40.734 18.661 ;
     RECT  41.76 17.741 42.174 18.667 ;
     RECT  39.384 18.661 40.878 18.761 ;
     RECT  39.384 18.761 40.698 18.959 ;
     RECT  41.616 18.667 42.174 18.995 ;
     RECT  7.815 2.413 8.097 19.003 ;
     RECT  35.928 18.661 35.946 19.139 ;
     RECT  41.616 18.995 41.634 19.147 ;
     RECT  9.972 17.077 9.99 19.237 ;
     RECT  38.592 19.381 38.61 19.499 ;
     RECT  39.42 18.959 40.698 19.499 ;
     RECT  9.684 19.237 9.99 19.543 ;
     RECT  10.908 18.661 24.426 19.543 ;
     RECT  34.815 15.863 35.097 19.651 ;
     RECT  41.58 19.147 41.634 19.723 ;
     RECT  41.58 19.723 42.174 19.769 ;
     RECT  41.58 19.769 41.778 20.039 ;
     RECT  36.504 19.921 36.522 20.075 ;
     RECT  6.984 19.507 7.002 20.119 ;
     RECT  34.776 19.651 35.097 20.345 ;
     RECT  4.608 19.579 4.626 20.353 ;
     RECT  39.42 19.499 40.497 20.425 ;
     RECT  39.42 20.425 40.698 20.461 ;
     RECT  39.384 20.461 40.698 20.551 ;
     RECT  4.608 20.353 5.094 20.623 ;
     RECT  5.904 20.317 5.922 20.623 ;
     RECT  38.988 20.551 40.698 20.651 ;
     RECT  41.616 20.039 41.778 20.723 ;
     RECT  38.052 20.551 38.07 21.001 ;
     RECT  37.044 20.461 37.062 21.155 ;
     RECT  38.052 21.001 38.214 21.227 ;
     RECT  26.676 21.199 26.694 21.271 ;
     RECT  42.12 20.971 42.174 21.271 ;
     RECT  26.676 21.271 26.766 21.299 ;
     RECT  25.236 2.731 25.254 21.389 ;
     RECT  26.748 21.299 26.766 21.533 ;
     RECT  42.12 21.271 42.21 21.677 ;
     RECT  38.196 21.227 38.214 21.811 ;
     RECT  39.384 20.651 40.698 21.811 ;
     RECT  38.196 21.811 40.698 21.929 ;
     RECT  2.415 2.413 2.697 21.937 ;
     RECT  4.608 20.623 5.922 21.973 ;
     RECT  6.876 20.119 7.002 21.973 ;
     RECT  2.376 21.937 2.697 22.027 ;
     RECT  4.608 21.973 7.002 22.081 ;
     RECT  38.7 21.929 40.698 22.109 ;
     RECT  41.544 21.931 41.634 22.109 ;
     RECT  41.616 22.109 41.634 22.411 ;
     RECT  26.748 22.351 26.766 22.477 ;
     RECT  7.815 19.003 8.802 22.513 ;
     RECT  9.684 19.543 24.426 22.513 ;
     RECT  26.748 22.477 26.838 22.541 ;
     RECT  39.384 22.109 40.698 22.541 ;
     RECT  2.304 22.027 2.697 22.585 ;
     RECT  2.304 22.585 2.79 22.621 ;
     RECT  26.784 22.541 26.838 22.649 ;
     RECT  7.815 22.513 24.426 22.739 ;
     RECT  41.616 22.411 42.174 22.739 ;
     RECT  3.996 22.081 7.002 22.747 ;
     RECT  2.304 22.621 3.006 22.775 ;
     RECT  3.996 22.747 7.038 22.783 ;
     RECT  7.815 22.739 19.242 22.783 ;
     RECT  2.34 22.775 3.006 22.819 ;
     RECT  20.016 22.739 24.426 22.981 ;
     RECT  34.815 20.345 35.097 23.017 ;
     RECT  2.34 22.819 3.222 23.161 ;
     RECT  3.996 22.783 19.242 23.161 ;
     RECT  20.016 22.981 24.786 23.189 ;
     RECT  26.784 22.649 26.802 23.189 ;
     RECT  34.776 23.017 35.097 23.189 ;
     RECT  25.92 23.251 25.938 23.323 ;
     RECT  39.384 22.541 40.497 23.431 ;
     RECT  41.724 22.739 42.174 23.659 ;
     RECT  38.988 23.431 40.497 23.665 ;
     RECT  41.616 23.659 42.174 23.699 ;
     RECT  25.776 23.323 25.938 23.827 ;
     RECT  38.988 23.665 40.59 23.899 ;
     RECT  42.156 23.699 42.174 23.899 ;
     RECT  38.772 23.899 40.59 23.971 ;
     RECT  25.776 23.827 25.974 23.999 ;
     RECT  25.776 23.999 25.902 24.097 ;
     RECT  34.815 23.189 35.097 24.097 ;
     RECT  37.62 23.701 37.638 24.233 ;
     RECT  20.016 23.189 24.714 24.241 ;
     RECT  38.772 23.971 40.698 24.241 ;
     RECT  34.776 24.097 35.097 24.431 ;
     RECT  2.34 23.161 19.242 24.461 ;
     RECT  2.415 24.461 19.242 24.503 ;
     RECT  37.872 24.241 40.698 24.503 ;
     RECT  20.016 24.241 24.93 24.511 ;
     RECT  25.704 24.097 25.902 24.511 ;
     RECT  42.156 23.899 42.21 24.653 ;
     RECT  20.016 24.511 25.902 24.781 ;
     RECT  26.784 24.205 26.802 24.781 ;
     RECT  37.872 24.503 38.214 24.899 ;
     RECT  42.156 24.653 42.174 24.907 ;
     RECT  39.168 24.503 40.698 24.935 ;
     RECT  20.016 24.781 26.802 25.051 ;
     RECT  3.6 24.503 19.242 25.169 ;
     RECT  36.504 23.323 36.522 25.205 ;
     RECT  41.616 24.907 42.174 25.229 ;
     RECT  38.196 24.899 38.214 25.241 ;
     RECT  39.168 24.935 40.497 25.321 ;
     RECT  38.736 25.321 40.497 25.439 ;
     RECT  20.016 25.051 26.838 25.591 ;
     RECT  38.88 25.439 40.497 25.681 ;
     RECT  38.88 25.681 40.698 25.979 ;
     RECT  34.815 24.431 35.097 25.987 ;
     RECT  34.776 25.987 35.097 26.087 ;
     RECT  39.276 25.979 40.698 26.131 ;
     RECT  20.016 25.591 27.126 26.401 ;
     RECT  37.044 26.131 37.062 26.429 ;
     RECT  28.368 26.401 28.386 26.491 ;
     RECT  28.296 26.491 28.386 26.591 ;
     RECT  39.276 26.131 41.058 26.669 ;
     RECT  20.016 26.401 27.522 26.671 ;
     RECT  39.276 26.669 40.698 26.789 ;
     RECT  39.276 26.789 40.662 26.869 ;
     RECT  39.168 26.869 40.662 26.905 ;
     RECT  42.156 25.229 42.174 26.923 ;
     RECT  38.736 26.905 40.662 27.067 ;
     RECT  38.376 27.067 40.662 27.131 ;
     RECT  30.852 27.067 30.87 27.203 ;
     RECT  38.376 27.131 40.497 27.481 ;
     RECT  41.76 26.923 42.174 27.691 ;
     RECT  29.415 2.413 29.697 27.751 ;
     RECT  38.196 27.481 40.497 27.779 ;
     RECT  28.44 26.671 28.494 27.841 ;
     RECT  29.376 27.751 29.697 27.841 ;
     RECT  41.616 27.691 42.174 27.883 ;
     RECT  38.592 27.779 40.497 27.905 ;
     RECT  20.016 26.671 27.702 27.913 ;
     RECT  28.44 27.841 29.697 27.913 ;
     RECT  41.58 27.883 42.174 27.913 ;
     RECT  39.024 27.905 40.497 27.985 ;
     RECT  35.928 27.841 35.946 28.013 ;
     RECT  20.016 27.913 29.697 28.021 ;
     RECT  39.024 27.985 40.734 28.049 ;
     RECT  30.672 27.985 30.69 28.139 ;
     RECT  41.58 27.913 42.21 28.205 ;
     RECT  30.78 28.147 30.798 28.247 ;
     RECT  20.016 28.021 29.826 28.291 ;
     RECT  39.132 28.049 40.734 28.409 ;
     RECT  41.58 28.205 42.174 28.688 ;
     RECT  39.456 28.409 40.698 29.131 ;
     RECT  41.58 28.688 41.634 29.131 ;
     RECT  39.456 29.131 41.634 29.335 ;
     RECT  38.772 29.335 41.634 29.399 ;
     RECT  20.016 28.291 30.006 29.641 ;
     RECT  41.544 29.399 41.634 29.645 ;
     RECT  35.928 29.461 35.946 29.759 ;
     RECT  34.815 26.087 35.097 29.767 ;
     RECT  32.184 29.911 32.202 30.029 ;
     RECT  34.776 29.767 35.097 30.029 ;
     RECT  38.772 29.399 40.734 30.029 ;
     RECT  31.284 29.911 31.302 30.109 ;
     RECT  41.544 29.645 41.598 30.209 ;
     RECT  37.62 29.461 37.638 30.299 ;
     RECT  39.42 30.029 40.734 30.335 ;
     RECT  41.58 30.209 41.598 30.379 ;
     RECT  31.284 30.109 31.734 30.451 ;
     RECT  41.58 30.379 42.174 30.721 ;
     RECT  41.58 30.721 42.21 30.893 ;
     RECT  38.484 30.541 38.502 30.991 ;
     RECT  39.42 30.335 40.59 30.991 ;
     RECT  38.484 30.991 40.59 31.153 ;
     RECT  30.96 30.451 31.734 31.261 ;
     RECT  32.796 30.991 32.814 31.351 ;
     RECT  32.796 31.351 33.066 31.387 ;
     RECT  41.58 30.893 41.634 31.435 ;
     RECT  38.196 31.153 40.59 31.451 ;
     RECT  38.772 31.451 40.59 31.495 ;
     RECT  32.796 31.387 33.39 31.559 ;
     RECT  34.815 30.029 35.097 31.657 ;
     RECT  41.544 31.435 41.634 31.829 ;
     RECT  42.984 31.891 43.002 31.949 ;
     RECT  3.672 25.169 19.242 31.955 ;
     RECT  38.772 31.495 40.698 31.991 ;
     RECT  39.024 31.991 40.698 32.189 ;
     RECT  34.776 31.657 35.097 32.341 ;
     RECT  36.504 31.801 36.522 32.369 ;
     RECT  37.62 32.071 37.638 32.431 ;
     RECT  37.62 32.431 38.214 32.459 ;
     RECT  32.796 31.559 33.21 32.611 ;
     RECT  42.156 32.107 42.174 32.683 ;
     RECT  41.58 32.683 42.174 32.801 ;
     RECT  34.236 32.341 35.097 32.809 ;
     RECT  38.196 32.459 38.214 32.809 ;
     RECT  38.196 32.809 38.286 32.909 ;
     RECT  39.6 32.189 40.698 33.007 ;
     RECT  34.2 32.809 35.097 33.043 ;
     RECT  39.384 33.007 40.698 33.377 ;
     RECT  42.156 32.801 42.174 33.421 ;
     RECT  33.984 33.043 35.097 33.583 ;
     RECT  42.156 33.421 42.21 33.677 ;
     RECT  37.008 33.421 37.026 33.809 ;
     RECT  39.384 33.377 40.626 33.925 ;
     RECT  42.156 33.677 42.174 33.925 ;
     RECT  33.984 33.583 35.334 33.961 ;
     RECT  41.616 33.925 42.174 33.965 ;
     RECT  33.984 33.961 35.55 34.159 ;
     RECT  37.908 33.781 37.926 34.159 ;
     RECT  37.584 34.159 37.926 34.501 ;
     RECT  39.132 33.925 40.626 34.501 ;
     RECT  39.132 34.501 40.734 34.591 ;
     RECT  38.916 34.591 40.734 34.637 ;
     RECT  37.584 34.501 38.178 34.735 ;
     RECT  41.724 33.965 42.174 34.735 ;
     RECT  36.756 34.735 38.178 35.041 ;
     RECT  39.204 34.637 40.734 35.195 ;
     RECT  36.612 35.041 38.178 35.311 ;
     RECT  41.724 34.735 42.21 35.311 ;
     RECT  36.612 35.311 38.286 35.401 ;
     RECT  39.204 35.195 40.698 35.401 ;
     RECT  41.616 35.311 42.21 35.509 ;
     RECT  41.616 35.509 42.246 35.885 ;
     RECT  36.612 35.401 40.698 36.121 ;
     RECT  42.192 35.885 42.246 36.365 ;
     RECT  42.192 36.365 42.21 36.653 ;
     RECT  36.612 36.121 40.77 36.661 ;
     RECT  33.984 34.159 35.694 36.895 ;
     RECT  36.612 36.661 40.842 36.895 ;
     RECT  33.984 36.895 40.842 37.021 ;
     RECT  32.76 32.611 33.21 37.165 ;
     RECT  42.156 36.907 42.174 37.399 ;
     RECT  33.984 37.021 40.914 37.421 ;
     RECT  32.688 37.165 33.21 37.561 ;
     RECT  33.984 37.421 40.698 37.561 ;
     RECT  32.688 37.561 40.698 37.613 ;
     RECT  20.016 29.641 30.186 37.831 ;
     RECT  30.96 31.261 31.914 37.831 ;
     RECT  3.744 31.955 19.242 37.903 ;
     RECT  20.016 37.831 31.914 37.903 ;
     RECT  3.744 37.903 31.914 38.011 ;
     RECT  32.688 37.613 33.21 38.011 ;
     RECT  42.156 37.399 42.246 38.201 ;
     RECT  3.744 38.011 33.21 38.245 ;
     RECT  33.984 37.613 40.698 38.371 ;
     RECT  33.984 38.371 40.77 38.551 ;
     RECT  42.192 38.201 42.246 38.669 ;
     RECT  2.415 24.503 2.697 38.677 ;
     RECT  3.672 38.245 33.21 38.677 ;
     RECT  2.415 38.677 2.754 38.713 ;
     RECT  3.6 38.677 33.21 38.713 ;
     RECT  33.984 38.551 40.878 38.713 ;
     RECT  2.415 38.713 33.21 38.785 ;
     RECT  33.984 38.713 40.914 38.785 ;
     RECT  2.415 38.785 40.914 39.119 ;
     RECT  32.796 39.119 40.914 39.149 ;
     RECT  42.192 38.669 42.21 39.437 ;
     RECT  2.415 39.119 31.986 39.901 ;
     RECT  32.796 39.149 40.77 39.901 ;
     RECT  42.156 39.595 42.174 40.019 ;
     RECT  2.415 39.901 40.77 40.325 ;
     RECT  2.415 40.325 40.698 40.405 ;
     RECT  43.02 38.479 43.038 40.459 ;
     RECT  41.616 40.075 41.634 40.469 ;
     RECT  2.268 40.405 40.698 40.493 ;
     RECT  42.948 40.459 43.038 40.493 ;
     RECT  42.948 40.493 42.966 40.685 ;
     RECT  2.376 40.493 40.698 40.829 ;
     RECT  16.884 40.829 40.698 40.901 ;
     RECT  14.832 40.829 15.966 40.979 ;
     RECT  2.376 40.829 3.546 41.021 ;
     RECT  4.284 40.829 5.454 41.021 ;
     RECT  6.336 40.829 10.458 41.021 ;
     RECT  11.592 40.829 14.094 41.021 ;
     RECT  14.832 40.979 15.858 41.021 ;
     RECT  16.884 40.901 37.458 41.021 ;
     RECT  38.628 40.901 40.698 41.021 ;
     RECT  29.415 41.021 29.646 41.057 ;
     RECT  34.815 41.021 34.974 41.057 ;
     RECT  2.376 41.021 2.682 41.165 ;
     RECT  7.776 41.021 8.154 41.165 ;
     RECT  23.976 41.021 24.174 41.165 ;
     RECT  34.956 41.057 34.974 41.165 ;
     RECT  2.376 41.165 2.394 41.213 ;
     RECT  7.776 41.165 7.794 41.213 ;
     RECT  13.176 41.021 13.662 41.213 ;
     RECT  18.216 41.021 18.774 41.213 ;
     RECT  23.976 41.165 23.994 41.213 ;
     RECT  29.556 41.057 29.646 41.213 ;
     RECT  38.628 41.021 40.374 41.213 ;
     RECT  9.108 41.021 9.126 41.645 ;
     RECT  15.84 41.021 15.858 41.645 ;
     RECT  18.216 41.213 18.594 41.645 ;
     RECT  26.208 41.021 26.226 41.645 ;
     RECT  31.716 41.021 31.734 41.645 ;
     RECT  33.408 41.021 33.426 41.645 ;
     RECT  12.348 41.021 12.366 42.221 ;
     RECT  13.644 41.213 13.662 42.221 ;
     RECT  18.216 41.645 18.234 42.221 ;
     RECT  29.628 41.213 29.646 42.221 ;
     RECT  30.744 41.021 30.762 42.221 ;
     RECT  37.44 41.021 37.458 42.221 ;
     RECT  38.628 41.213 39.582 42.221 ;
     RECT  40.356 41.213 40.374 42.221 ;
     RECT  38.628 42.221 38.646 42.269 ;
     RECT  39.564 42.221 39.582 42.269 ;
    LAYER M4 ;
     RECT  0.156 21.12 0.275 22.056 ;
     RECT  2.245 40.464 2.365 40.488 ;
     RECT  0.275 22.032 2.408 22.056 ;
     RECT  2.329 24.432 2.408 24.456 ;
     RECT  0.229 32.256 2.408 32.28 ;
     RECT  2.365 40.464 2.408 41.208 ;
     RECT  2.408 2.148 2.483 41.208 ;
     RECT  2.483 2.148 2.512 41.16 ;
     RECT  2.512 2.418 2.704 41.16 ;
     RECT  2.704 40.464 2.716 41.16 ;
     RECT  2.716 40.464 3.413 41.016 ;
     RECT  2.704 38.688 3.805 39.096 ;
     RECT  3.805 38.688 3.949 39.24 ;
     RECT  3.413 40.704 4.597 41.016 ;
     RECT  3.949 38.16 4.705 39.24 ;
     RECT  4.705 38.064 6.037 39.24 ;
     RECT  4.597 40.464 6.037 41.016 ;
     RECT  6.037 38.064 6.653 41.016 ;
     RECT  6.653 40.464 7.724 41.016 ;
     RECT  6.653 38.064 7.765 38.712 ;
     RECT  2.704 24.432 7.808 24.456 ;
     RECT  2.704 32.256 7.808 32.28 ;
     RECT  7.669 36.912 7.808 36.936 ;
     RECT  7.765 38.064 7.808 39.096 ;
     RECT  7.724 40.464 7.808 41.208 ;
     RECT  7.808 2.148 7.811 41.208 ;
     RECT  7.811 2.148 7.912 41.16 ;
     RECT  7.912 2.418 8.104 41.16 ;
     RECT  8.104 36.912 8.777 39.096 ;
     RECT  8.104 24.432 8.819 24.456 ;
     RECT  8.777 37.296 9.029 39.096 ;
     RECT  8.104 40.992 9.068 41.16 ;
     RECT  9.029 37.584 9.107 39.096 ;
     RECT  9.107 38.16 9.137 39.096 ;
     RECT  9.068 40.992 9.155 41.64 ;
     RECT  9.155 40.992 9.301 41.016 ;
     RECT  9.301 40.704 10.033 41.016 ;
     RECT  9.137 38.16 10.145 38.856 ;
     RECT  10.033 39.888 10.361 41.016 ;
     RECT  10.361 40.464 10.499 41.016 ;
     RECT  10.499 40.464 10.757 40.728 ;
     RECT  10.757 40.704 10.979 40.728 ;
     RECT  11.581 40.992 12.133 41.016 ;
     RECT  12.337 42.192 12.563 42.216 ;
     RECT  12.133 40.464 12.949 41.016 ;
     RECT  12.949 39.744 13.148 41.016 ;
     RECT  8.104 32.256 13.208 32.28 ;
     RECT  10.145 38.16 13.208 38.184 ;
     RECT  13.148 39.744 13.208 41.208 ;
     RECT  13.208 2.148 13.235 41.208 ;
     RECT  13.235 2.148 13.312 41.16 ;
     RECT  13.312 2.418 13.504 41.16 ;
     RECT  13.504 38.16 13.565 41.16 ;
     RECT  13.628 42.192 13.715 42.216 ;
     RECT  13.565 38.16 14.821 41.016 ;
     RECT  14.821 37.968 14.897 41.016 ;
     RECT  14.897 40.464 15.347 41.016 ;
     RECT  15.347 40.704 15.829 41.016 ;
     RECT  15.829 40.704 16.019 41.64 ;
     RECT  14.897 37.968 16.193 38.664 ;
     RECT  16.019 40.704 16.211 41.016 ;
     RECT  16.211 40.992 17.276 41.016 ;
     RECT  16.193 37.968 17.516 37.992 ;
     RECT  17.449 39.072 17.516 39.096 ;
     RECT  17.516 37.968 17.557 39.096 ;
     RECT  17.276 40.704 17.557 41.016 ;
     RECT  18.205 42.192 18.323 42.216 ;
     RECT  17.557 37.968 18.565 41.016 ;
     RECT  18.38 18.192 18.608 18.216 ;
     RECT  13.504 32.256 18.608 32.28 ;
     RECT  18.565 37.968 18.608 41.64 ;
     RECT  18.608 2.148 18.712 41.64 ;
     RECT  18.712 2.418 18.904 41.64 ;
     RECT  18.904 37.968 18.995 41.64 ;
     RECT  18.995 37.968 19.541 41.016 ;
     RECT  19.541 38.16 19.801 41.016 ;
     RECT  19.801 38.16 19.865 39.096 ;
     RECT  19.865 38.16 19.973 38.712 ;
     RECT  18.904 32.256 20.945 32.28 ;
     RECT  21.157 32.448 21.241 32.472 ;
     RECT  21.625 39.456 22.028 39.48 ;
     RECT  19.973 38.16 22.237 38.184 ;
     RECT  22.028 39.264 22.237 39.48 ;
     RECT  22.237 38.16 22.669 39.48 ;
     RECT  22.669 37.968 23.132 39.48 ;
     RECT  19.801 40.464 23.132 41.016 ;
     RECT  23.132 37.968 23.948 41.016 ;
     RECT  23.948 37.968 24.008 41.208 ;
     RECT  24.008 2.148 24.035 41.208 ;
     RECT  24.035 2.148 24.112 41.16 ;
     RECT  24.112 2.418 24.227 41.16 ;
     RECT  24.227 2.418 24.304 41.016 ;
     RECT  24.304 37.968 24.515 39.144 ;
     RECT  24.515 37.968 25.049 38.808 ;
     RECT  24.304 40.464 25.187 41.016 ;
     RECT  25.049 37.968 26.161 37.992 ;
     RECT  25.187 40.992 26.197 41.016 ;
     RECT  26.197 40.992 26.339 41.64 ;
     RECT  26.161 37.968 26.813 38.328 ;
     RECT  26.125 39.36 26.813 39.384 ;
     RECT  26.339 40.992 26.845 41.016 ;
     RECT  26.845 40.704 27.011 41.016 ;
     RECT  26.813 37.968 27.845 37.992 ;
     RECT  27.845 37.968 27.929 38.808 ;
     RECT  27.011 40.992 28.076 41.016 ;
     RECT  28.076 40.704 28.105 41.016 ;
     RECT  27.929 37.968 29.408 37.992 ;
     RECT  28.105 39.888 29.408 41.016 ;
     RECT  29.408 2.148 29.461 41.052 ;
     RECT  29.461 2.148 29.512 41.208 ;
     RECT  29.512 2.418 29.585 41.208 ;
     RECT  29.612 42.192 29.699 42.216 ;
     RECT  29.585 2.418 29.704 41.016 ;
     RECT  29.704 37.968 30.769 38.424 ;
     RECT  30.733 42.192 30.851 42.216 ;
     RECT  30.769 37.968 31.085 38.712 ;
     RECT  31.085 37.968 31.169 39.384 ;
     RECT  29.704 40.464 31.331 41.016 ;
     RECT  31.331 40.704 31.705 41.016 ;
     RECT  31.705 40.704 32.195 41.64 ;
     RECT  32.195 40.704 32.387 41.016 ;
     RECT  31.169 37.968 32.636 38.808 ;
     RECT  32.636 37.584 33.001 38.808 ;
     RECT  33.001 37.008 33.013 38.808 ;
     RECT  33.013 37.008 33.059 39.192 ;
     RECT  33.059 38.784 33.073 39.192 ;
     RECT  33.059 37.008 33.085 37.608 ;
     RECT  33.073 38.784 33.113 39.336 ;
     RECT  32.387 40.992 33.397 41.016 ;
     RECT  33.397 40.992 33.683 41.64 ;
     RECT  33.113 38.832 34.153 39.336 ;
     RECT  33.683 40.992 34.309 41.016 ;
     RECT  33.085 37.584 34.549 37.608 ;
     RECT  34.153 38.64 34.549 39.336 ;
     RECT  34.549 37.584 34.808 39.336 ;
     RECT  34.309 40.464 34.808 41.016 ;
     RECT  34.808 2.148 34.912 41.052 ;
     RECT  34.912 2.418 34.94 41.052 ;
     RECT  34.94 2.418 35.027 41.16 ;
     RECT  35.027 2.418 35.104 41.016 ;
     RECT  35.104 37.584 35.885 39.288 ;
     RECT  35.885 37.584 36.169 38.232 ;
     RECT  35.885 39.264 36.431 39.288 ;
     RECT  36.169 37.536 36.713 38.232 ;
     RECT  35.104 40.464 37.043 41.016 ;
     RECT  36.431 39.264 37.045 39.384 ;
     RECT  37.043 40.464 37.045 40.728 ;
     RECT  37.045 39.264 37.091 40.728 ;
     RECT  36.713 37.536 37.213 38.184 ;
     RECT  37.213 36.72 37.433 38.184 ;
     RECT  37.091 39.36 37.523 40.728 ;
     RECT  37.429 42.192 37.715 42.216 ;
     RECT  37.433 36.72 37.825 37.08 ;
     RECT  37.964 34.512 38.051 34.536 ;
     RECT  37.433 38.16 38.177 38.184 ;
     RECT  37.523 39.36 38.177 40.488 ;
     RECT  38.149 34.608 38.233 34.776 ;
     RECT  37.825 36.24 38.284 37.08 ;
     RECT  38.177 38.16 38.549 40.488 ;
     RECT  38.549 38.64 38.675 40.488 ;
     RECT  38.617 42.24 38.689 42.264 ;
     RECT  38.675 38.64 38.771 40.44 ;
     RECT  38.689 42.192 39.481 42.264 ;
     RECT  38.771 38.688 39.781 40.44 ;
     RECT  39.481 41.616 40.019 42.264 ;
     RECT  39.781 38.688 40.093 40.488 ;
     RECT  39.877 26.736 40.208 26.76 ;
     RECT  38.233 34.608 40.208 34.632 ;
     RECT  38.284 36.24 40.208 36.264 ;
     RECT  38.725 37.296 40.208 37.608 ;
     RECT  40.093 38.688 40.208 41.208 ;
     RECT  40.208 2.148 40.211 41.208 ;
     RECT  40.211 2.148 40.312 41.052 ;
     RECT  40.019 42.192 40.499 42.264 ;
     RECT  40.312 2.418 40.504 41.016 ;
     RECT  40.499 42.24 40.691 42.264 ;
     RECT  40.504 40.848 40.883 41.016 ;
     RECT  40.504 29.136 41.533 29.16 ;
     RECT  41.533 2.256 41.569 2.28 ;
     RECT  41.533 29.136 41.569 29.928 ;
     RECT  40.504 8.016 41.605 8.04 ;
     RECT  40.504 10.224 41.605 11.016 ;
     RECT  41.569 14.448 41.605 14.472 ;
     RECT  41.569 19.152 41.605 19.944 ;
     RECT  41.533 21.936 41.605 21.96 ;
     RECT  40.504 26.16 41.605 26.664 ;
     RECT  41.569 27.888 41.605 27.912 ;
     RECT  41.569 29.136 41.605 30.216 ;
     RECT  41.533 31.44 41.605 31.464 ;
     RECT  40.504 38.832 41.605 39.144 ;
     RECT  40.883 40.848 41.605 40.872 ;
     RECT  41.605 14.16 41.713 14.472 ;
     RECT  41.605 33.936 41.713 33.96 ;
     RECT  41.605 35.376 41.713 35.88 ;
     RECT  41.713 13.2 41.749 14.472 ;
     RECT  41.569 15.696 41.749 17.448 ;
     RECT  41.605 18.672 41.749 20.712 ;
     RECT  41.605 24.912 41.749 26.664 ;
     RECT  41.605 27.696 41.749 31.656 ;
     RECT  41.569 2.256 41.785 2.76 ;
     RECT  41.605 8.016 42.109 11.016 ;
     RECT  41.749 12.432 42.109 14.472 ;
     RECT  41.749 15.696 42.109 20.712 ;
     RECT  41.605 21.936 42.109 23.688 ;
     RECT  41.605 4.272 42.145 4.968 ;
     RECT  40.504 6 42.145 6.792 ;
     RECT  42.109 8.016 42.145 23.688 ;
     RECT  41.749 24.912 42.145 31.656 ;
     RECT  41.569 32.688 42.145 32.712 ;
     RECT  41.713 33.936 42.145 35.88 ;
     RECT  40.504 37.104 42.145 37.608 ;
     RECT  41.605 38.832 42.145 40.872 ;
     RECT  41.785 2.256 42.181 3.048 ;
     RECT  42.145 4.272 42.181 35.88 ;
     RECT  42.145 36.912 42.181 40.872 ;
     RECT  42.181 2.256 43.02 40.872 ;
     RECT  43.02 40.464 43.049 40.488 ;
    LAYER M5 ;
     RECT  2.4 2.137 2.52 2.151 ;
     RECT  7.8 2.137 7.92 2.151 ;
     RECT  13.2 2.137 13.32 2.151 ;
     RECT  18.6 2.137 18.72 2.151 ;
     RECT  24 2.137 24.12 2.151 ;
     RECT  29.4 2.137 29.52 2.151 ;
     RECT  34.8 2.137 34.92 2.151 ;
     RECT  40.2 2.137 40.32 2.151 ;
     RECT  18.6 2.151 18.912 18.181 ;
     RECT  7.8 2.151 8.112 24.421 ;
     RECT  0.24 21.109 0.264 32.291 ;
     RECT  38.016 34.501 38.04 34.741 ;
     RECT  38.016 34.741 38.184 36.229 ;
     RECT  7.8 24.421 8.808 36.901 ;
     RECT  38.016 36.229 38.232 37.091 ;
     RECT  38.16 37.091 38.232 37.285 ;
     RECT  40.2 2.151 40.512 37.429 ;
     RECT  7.68 36.901 8.808 37.573 ;
     RECT  33.024 36.997 33.048 37.573 ;
     RECT  38.16 37.285 38.76 37.573 ;
     RECT  39.84 37.429 40.512 37.573 ;
     RECT  24 2.151 24.312 37.957 ;
     RECT  32.688 37.573 33.048 38.003 ;
     RECT  7.68 37.573 9.096 38.099 ;
     RECT  13.2 2.151 13.512 38.149 ;
     RECT  34.8 2.151 35.112 38.149 ;
     RECT  7.8 38.099 9.096 38.195 ;
     RECT  21.168 32.437 21.192 38.195 ;
     RECT  18.432 18.181 18.912 38.243 ;
     RECT  23.184 37.957 24.312 38.581 ;
     RECT  15.792 38.053 15.816 38.675 ;
     RECT  34.56 38.149 35.112 38.675 ;
     RECT  38.16 37.573 40.512 38.675 ;
     RECT  18.6 38.243 18.912 38.677 ;
     RECT  13.2 38.149 14.328 38.819 ;
     RECT  27.888 37.957 27.912 38.819 ;
     RECT  10.08 38.149 10.104 38.867 ;
     RECT  38.16 38.675 38.232 38.867 ;
     RECT  23.088 38.581 24.312 39.109 ;
     RECT  33.024 38.003 33.048 39.203 ;
     RECT  36.48 37.525 36.504 39.253 ;
     RECT  31.104 38.677 31.128 39.395 ;
     RECT  36.48 39.253 37.08 39.395 ;
     RECT  38.16 38.867 38.184 39.395 ;
     RECT  39.312 38.675 40.512 40.405 ;
     RECT  2.4 2.151 2.712 40.453 ;
     RECT  7.8 38.195 8.112 40.453 ;
     RECT  13.2 38.819 13.512 40.453 ;
     RECT  14.784 39.829 14.808 40.453 ;
     RECT  17.568 38.581 17.592 40.453 ;
     RECT  18.6 38.677 19.752 40.453 ;
     RECT  22.08 39.253 22.104 40.453 ;
     RECT  23.088 39.109 24.504 40.453 ;
     RECT  29.4 2.151 29.712 40.453 ;
     RECT  34.8 38.675 35.112 40.453 ;
     RECT  37.056 39.395 37.08 40.453 ;
     RECT  39.024 40.405 40.512 40.453 ;
     RECT  2.256 40.453 3.336 40.693 ;
     RECT  4.752 40.453 5.16 40.693 ;
     RECT  10.272 40.453 10.68 40.693 ;
     RECT  12.144 40.453 15.336 40.693 ;
     RECT  17.568 40.453 22.104 40.693 ;
     RECT  29.4 40.453 31.32 40.693 ;
     RECT  2.256 40.693 5.16 40.981 ;
     RECT  6.144 40.453 8.112 40.981 ;
     RECT  9.312 40.693 10.968 40.981 ;
     RECT  12.144 40.693 16.2 40.981 ;
     RECT  17.328 40.693 22.104 40.981 ;
     RECT  23.088 40.453 25.176 40.981 ;
     RECT  26.976 40.693 27 40.981 ;
     RECT  28.128 40.693 31.32 40.981 ;
     RECT  32.352 40.693 32.376 40.981 ;
     RECT  34.32 40.453 40.512 40.981 ;
     RECT  2.256 40.981 40.872 43.024 ;
     RECT  38.76 37.285 40.2 37.429 ;
     RECT  38.76 37.429 39.84 37.573 ;
     RECT  35.112 37.525 36.48 39.395 ;
     RECT  27.912 37.957 29.4 38.819 ;
     RECT  9.096 38.149 10.08 38.195 ;
     RECT  14.328 38.149 15.792 38.675 ;
     RECT  33.048 38.149 34.56 38.675 ;
     RECT  18.432 38.243 18.6 38.581 ;
     RECT  17.592 38.581 18.6 40.453 ;
     RECT  14.328 38.675 14.808 38.819 ;
     RECT  38.232 38.675 39.312 38.867 ;
     RECT  29.712 38.677 31.104 39.395 ;
     RECT  13.512 38.819 14.808 39.829 ;
     RECT  38.184 38.867 39.312 39.395 ;
     RECT  22.104 39.253 23.088 40.981 ;
     RECT  37.08 39.253 38.16 39.395 ;
     RECT  29.712 39.395 31.128 40.453 ;
     RECT  35.112 39.395 37.056 40.453 ;
     RECT  37.08 39.395 39.312 40.405 ;
     RECT  13.512 39.829 14.784 40.453 ;
     RECT  37.08 40.405 39.024 40.453 ;
     RECT  3.336 40.453 4.752 40.693 ;
     RECT  5.16 40.453 6.144 40.981 ;
     RECT  10.68 40.453 12.144 40.693 ;
     RECT  8.112 40.693 9.312 40.981 ;
     RECT  10.968 40.693 12.144 40.981 ;
     RECT  16.2 40.693 17.328 40.981 ;
     RECT  27 40.693 28.128 40.981 ;
     RECT  31.32 40.693 32.352 40.981 ;
  END
END dsfd_vm_static_write_capture128
END LIBRARY
